VERSION 5.7 ;
BUSBITCHARS "[]" ;
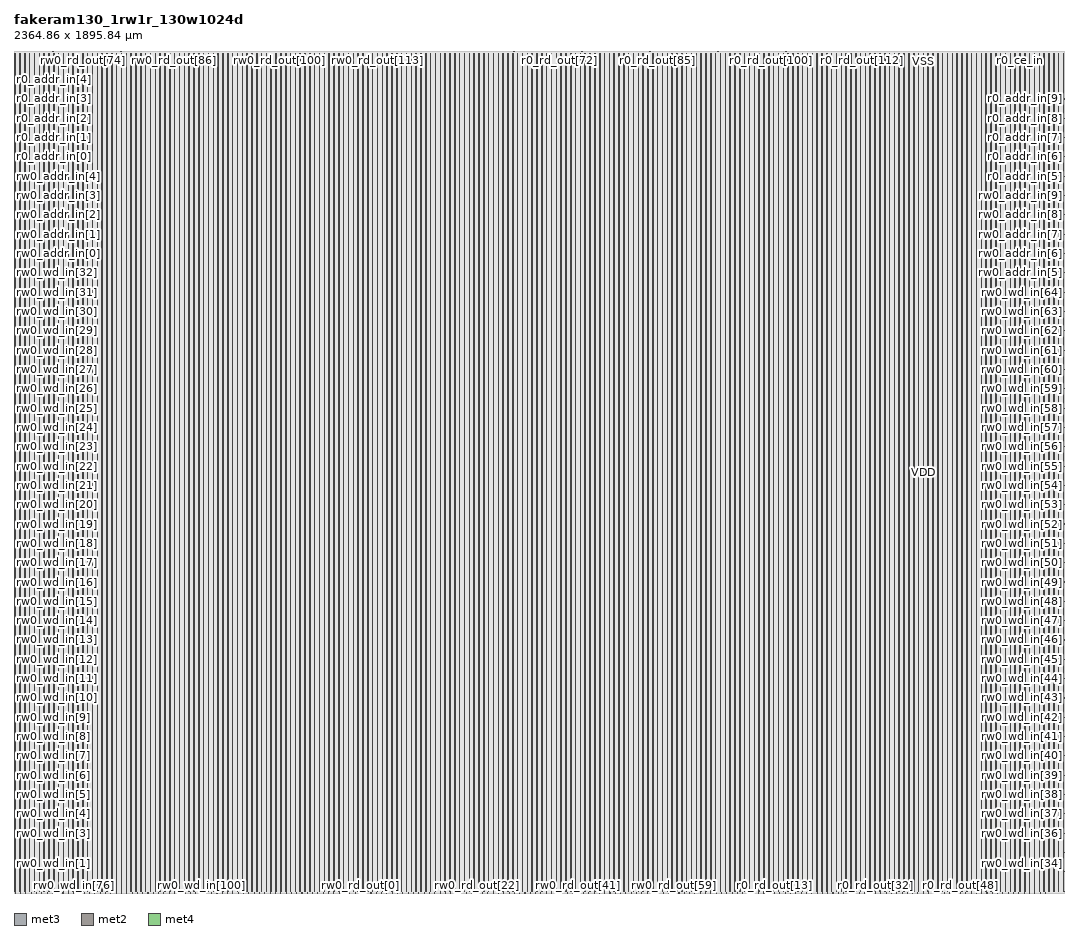
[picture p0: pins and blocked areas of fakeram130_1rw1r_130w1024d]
MACRO fakeram130_1rw1r_130w1024d
  FOREIGN fakeram130_1rw1r_130w1024d 0 0 ;
  SYMMETRY X Y R90 ;
  SIZE 2364.860 BY 1895.840 ;
  CLASS BLOCK ;
  PIN rw0_wd_in[0]
    DIRECTION INPUT ;
    USE SIGNAL ;
    SHAPE ABUTMENT ;
    PORT
      LAYER met3 ;
      RECT 0.000 3.930 0.900 4.230 ;
    END
  END rw0_wd_in[0]
  PIN rw0_wd_in[1]
    DIRECTION INPUT ;
    USE SIGNAL ;
    SHAPE ABUTMENT ;
    PORT
      LAYER met3 ;
      RECT 0.000 47.450 0.900 47.750 ;
    END
  END rw0_wd_in[1]
  PIN rw0_wd_in[2]
    DIRECTION INPUT ;
    USE SIGNAL ;
    SHAPE ABUTMENT ;
    PORT
      LAYER met3 ;
      RECT 0.000 90.970 0.900 91.270 ;
    END
  END rw0_wd_in[2]
  PIN rw0_wd_in[3]
    DIRECTION INPUT ;
    USE SIGNAL ;
    SHAPE ABUTMENT ;
    PORT
      LAYER met3 ;
      RECT 0.000 134.490 0.900 134.790 ;
    END
  END rw0_wd_in[3]
  PIN rw0_wd_in[4]
    DIRECTION INPUT ;
    USE SIGNAL ;
    SHAPE ABUTMENT ;
    PORT
      LAYER met3 ;
      RECT 0.000 178.010 0.900 178.310 ;
    END
  END rw0_wd_in[4]
  PIN rw0_wd_in[5]
    DIRECTION INPUT ;
    USE SIGNAL ;
    SHAPE ABUTMENT ;
    PORT
      LAYER met3 ;
      RECT 0.000 221.530 0.900 221.830 ;
    END
  END rw0_wd_in[5]
  PIN rw0_wd_in[6]
    DIRECTION INPUT ;
    USE SIGNAL ;
    SHAPE ABUTMENT ;
    PORT
      LAYER met3 ;
      RECT 0.000 265.050 0.900 265.350 ;
    END
  END rw0_wd_in[6]
  PIN rw0_wd_in[7]
    DIRECTION INPUT ;
    USE SIGNAL ;
    SHAPE ABUTMENT ;
    PORT
      LAYER met3 ;
      RECT 0.000 308.570 0.900 308.870 ;
    END
  END rw0_wd_in[7]
  PIN rw0_wd_in[8]
    DIRECTION INPUT ;
    USE SIGNAL ;
    SHAPE ABUTMENT ;
    PORT
      LAYER met3 ;
      RECT 0.000 352.090 0.900 352.390 ;
    END
  END rw0_wd_in[8]
  PIN rw0_wd_in[9]
    DIRECTION INPUT ;
    USE SIGNAL ;
    SHAPE ABUTMENT ;
    PORT
      LAYER met3 ;
      RECT 0.000 395.610 0.900 395.910 ;
    END
  END rw0_wd_in[9]
  PIN rw0_wd_in[10]
    DIRECTION INPUT ;
    USE SIGNAL ;
    SHAPE ABUTMENT ;
    PORT
      LAYER met3 ;
      RECT 0.000 439.130 0.900 439.430 ;
    END
  END rw0_wd_in[10]
  PIN rw0_wd_in[11]
    DIRECTION INPUT ;
    USE SIGNAL ;
    SHAPE ABUTMENT ;
    PORT
      LAYER met3 ;
      RECT 0.000 482.650 0.900 482.950 ;
    END
  END rw0_wd_in[11]
  PIN rw0_wd_in[12]
    DIRECTION INPUT ;
    USE SIGNAL ;
    SHAPE ABUTMENT ;
    PORT
      LAYER met3 ;
      RECT 0.000 526.170 0.900 526.470 ;
    END
  END rw0_wd_in[12]
  PIN rw0_wd_in[13]
    DIRECTION INPUT ;
    USE SIGNAL ;
    SHAPE ABUTMENT ;
    PORT
      LAYER met3 ;
      RECT 0.000 569.690 0.900 569.990 ;
    END
  END rw0_wd_in[13]
  PIN rw0_wd_in[14]
    DIRECTION INPUT ;
    USE SIGNAL ;
    SHAPE ABUTMENT ;
    PORT
      LAYER met3 ;
      RECT 0.000 613.210 0.900 613.510 ;
    END
  END rw0_wd_in[14]
  PIN rw0_wd_in[15]
    DIRECTION INPUT ;
    USE SIGNAL ;
    SHAPE ABUTMENT ;
    PORT
      LAYER met3 ;
      RECT 0.000 656.730 0.900 657.030 ;
    END
  END rw0_wd_in[15]
  PIN rw0_wd_in[16]
    DIRECTION INPUT ;
    USE SIGNAL ;
    SHAPE ABUTMENT ;
    PORT
      LAYER met3 ;
      RECT 0.000 700.250 0.900 700.550 ;
    END
  END rw0_wd_in[16]
  PIN rw0_wd_in[17]
    DIRECTION INPUT ;
    USE SIGNAL ;
    SHAPE ABUTMENT ;
    PORT
      LAYER met3 ;
      RECT 0.000 743.770 0.900 744.070 ;
    END
  END rw0_wd_in[17]
  PIN rw0_wd_in[18]
    DIRECTION INPUT ;
    USE SIGNAL ;
    SHAPE ABUTMENT ;
    PORT
      LAYER met3 ;
      RECT 0.000 787.290 0.900 787.590 ;
    END
  END rw0_wd_in[18]
  PIN rw0_wd_in[19]
    DIRECTION INPUT ;
    USE SIGNAL ;
    SHAPE ABUTMENT ;
    PORT
      LAYER met3 ;
      RECT 0.000 830.810 0.900 831.110 ;
    END
  END rw0_wd_in[19]
  PIN rw0_wd_in[20]
    DIRECTION INPUT ;
    USE SIGNAL ;
    SHAPE ABUTMENT ;
    PORT
      LAYER met3 ;
      RECT 0.000 874.330 0.900 874.630 ;
    END
  END rw0_wd_in[20]
  PIN rw0_wd_in[21]
    DIRECTION INPUT ;
    USE SIGNAL ;
    SHAPE ABUTMENT ;
    PORT
      LAYER met3 ;
      RECT 0.000 917.850 0.900 918.150 ;
    END
  END rw0_wd_in[21]
  PIN rw0_wd_in[22]
    DIRECTION INPUT ;
    USE SIGNAL ;
    SHAPE ABUTMENT ;
    PORT
      LAYER met3 ;
      RECT 0.000 961.370 0.900 961.670 ;
    END
  END rw0_wd_in[22]
  PIN rw0_wd_in[23]
    DIRECTION INPUT ;
    USE SIGNAL ;
    SHAPE ABUTMENT ;
    PORT
      LAYER met3 ;
      RECT 0.000 1004.890 0.900 1005.190 ;
    END
  END rw0_wd_in[23]
  PIN rw0_wd_in[24]
    DIRECTION INPUT ;
    USE SIGNAL ;
    SHAPE ABUTMENT ;
    PORT
      LAYER met3 ;
      RECT 0.000 1048.410 0.900 1048.710 ;
    END
  END rw0_wd_in[24]
  PIN rw0_wd_in[25]
    DIRECTION INPUT ;
    USE SIGNAL ;
    SHAPE ABUTMENT ;
    PORT
      LAYER met3 ;
      RECT 0.000 1091.930 0.900 1092.230 ;
    END
  END rw0_wd_in[25]
  PIN rw0_wd_in[26]
    DIRECTION INPUT ;
    USE SIGNAL ;
    SHAPE ABUTMENT ;
    PORT
      LAYER met3 ;
      RECT 0.000 1135.450 0.900 1135.750 ;
    END
  END rw0_wd_in[26]
  PIN rw0_wd_in[27]
    DIRECTION INPUT ;
    USE SIGNAL ;
    SHAPE ABUTMENT ;
    PORT
      LAYER met3 ;
      RECT 0.000 1178.970 0.900 1179.270 ;
    END
  END rw0_wd_in[27]
  PIN rw0_wd_in[28]
    DIRECTION INPUT ;
    USE SIGNAL ;
    SHAPE ABUTMENT ;
    PORT
      LAYER met3 ;
      RECT 0.000 1222.490 0.900 1222.790 ;
    END
  END rw0_wd_in[28]
  PIN rw0_wd_in[29]
    DIRECTION INPUT ;
    USE SIGNAL ;
    SHAPE ABUTMENT ;
    PORT
      LAYER met3 ;
      RECT 0.000 1266.010 0.900 1266.310 ;
    END
  END rw0_wd_in[29]
  PIN rw0_wd_in[30]
    DIRECTION INPUT ;
    USE SIGNAL ;
    SHAPE ABUTMENT ;
    PORT
      LAYER met3 ;
      RECT 0.000 1309.530 0.900 1309.830 ;
    END
  END rw0_wd_in[30]
  PIN rw0_wd_in[31]
    DIRECTION INPUT ;
    USE SIGNAL ;
    SHAPE ABUTMENT ;
    PORT
      LAYER met3 ;
      RECT 0.000 1353.050 0.900 1353.350 ;
    END
  END rw0_wd_in[31]
  PIN rw0_wd_in[32]
    DIRECTION INPUT ;
    USE SIGNAL ;
    SHAPE ABUTMENT ;
    PORT
      LAYER met3 ;
      RECT 0.000 1396.570 0.900 1396.870 ;
    END
  END rw0_wd_in[32]
  PIN rw0_wd_in[33]
    DIRECTION INPUT ;
    USE SIGNAL ;
    SHAPE ABUTMENT ;
    PORT
      LAYER met3 ;
      RECT 2363.960 3.930 2364.860 4.230 ;
    END
  END rw0_wd_in[33]
  PIN rw0_wd_in[34]
    DIRECTION INPUT ;
    USE SIGNAL ;
    SHAPE ABUTMENT ;
    PORT
      LAYER met3 ;
      RECT 2363.960 47.450 2364.860 47.750 ;
    END
  END rw0_wd_in[34]
  PIN rw0_wd_in[35]
    DIRECTION INPUT ;
    USE SIGNAL ;
    SHAPE ABUTMENT ;
    PORT
      LAYER met3 ;
      RECT 2363.960 90.970 2364.860 91.270 ;
    END
  END rw0_wd_in[35]
  PIN rw0_wd_in[36]
    DIRECTION INPUT ;
    USE SIGNAL ;
    SHAPE ABUTMENT ;
    PORT
      LAYER met3 ;
      RECT 2363.960 134.490 2364.860 134.790 ;
    END
  END rw0_wd_in[36]
  PIN rw0_wd_in[37]
    DIRECTION INPUT ;
    USE SIGNAL ;
    SHAPE ABUTMENT ;
    PORT
      LAYER met3 ;
      RECT 2363.960 178.010 2364.860 178.310 ;
    END
  END rw0_wd_in[37]
  PIN rw0_wd_in[38]
    DIRECTION INPUT ;
    USE SIGNAL ;
    SHAPE ABUTMENT ;
    PORT
      LAYER met3 ;
      RECT 2363.960 221.530 2364.860 221.830 ;
    END
  END rw0_wd_in[38]
  PIN rw0_wd_in[39]
    DIRECTION INPUT ;
    USE SIGNAL ;
    SHAPE ABUTMENT ;
    PORT
      LAYER met3 ;
      RECT 2363.960 265.050 2364.860 265.350 ;
    END
  END rw0_wd_in[39]
  PIN rw0_wd_in[40]
    DIRECTION INPUT ;
    USE SIGNAL ;
    SHAPE ABUTMENT ;
    PORT
      LAYER met3 ;
      RECT 2363.960 308.570 2364.860 308.870 ;
    END
  END rw0_wd_in[40]
  PIN rw0_wd_in[41]
    DIRECTION INPUT ;
    USE SIGNAL ;
    SHAPE ABUTMENT ;
    PORT
      LAYER met3 ;
      RECT 2363.960 352.090 2364.860 352.390 ;
    END
  END rw0_wd_in[41]
  PIN rw0_wd_in[42]
    DIRECTION INPUT ;
    USE SIGNAL ;
    SHAPE ABUTMENT ;
    PORT
      LAYER met3 ;
      RECT 2363.960 395.610 2364.860 395.910 ;
    END
  END rw0_wd_in[42]
  PIN rw0_wd_in[43]
    DIRECTION INPUT ;
    USE SIGNAL ;
    SHAPE ABUTMENT ;
    PORT
      LAYER met3 ;
      RECT 2363.960 439.130 2364.860 439.430 ;
    END
  END rw0_wd_in[43]
  PIN rw0_wd_in[44]
    DIRECTION INPUT ;
    USE SIGNAL ;
    SHAPE ABUTMENT ;
    PORT
      LAYER met3 ;
      RECT 2363.960 482.650 2364.860 482.950 ;
    END
  END rw0_wd_in[44]
  PIN rw0_wd_in[45]
    DIRECTION INPUT ;
    USE SIGNAL ;
    SHAPE ABUTMENT ;
    PORT
      LAYER met3 ;
      RECT 2363.960 526.170 2364.860 526.470 ;
    END
  END rw0_wd_in[45]
  PIN rw0_wd_in[46]
    DIRECTION INPUT ;
    USE SIGNAL ;
    SHAPE ABUTMENT ;
    PORT
      LAYER met3 ;
      RECT 2363.960 569.690 2364.860 569.990 ;
    END
  END rw0_wd_in[46]
  PIN rw0_wd_in[47]
    DIRECTION INPUT ;
    USE SIGNAL ;
    SHAPE ABUTMENT ;
    PORT
      LAYER met3 ;
      RECT 2363.960 613.210 2364.860 613.510 ;
    END
  END rw0_wd_in[47]
  PIN rw0_wd_in[48]
    DIRECTION INPUT ;
    USE SIGNAL ;
    SHAPE ABUTMENT ;
    PORT
      LAYER met3 ;
      RECT 2363.960 656.730 2364.860 657.030 ;
    END
  END rw0_wd_in[48]
  PIN rw0_wd_in[49]
    DIRECTION INPUT ;
    USE SIGNAL ;
    SHAPE ABUTMENT ;
    PORT
      LAYER met3 ;
      RECT 2363.960 700.250 2364.860 700.550 ;
    END
  END rw0_wd_in[49]
  PIN rw0_wd_in[50]
    DIRECTION INPUT ;
    USE SIGNAL ;
    SHAPE ABUTMENT ;
    PORT
      LAYER met3 ;
      RECT 2363.960 743.770 2364.860 744.070 ;
    END
  END rw0_wd_in[50]
  PIN rw0_wd_in[51]
    DIRECTION INPUT ;
    USE SIGNAL ;
    SHAPE ABUTMENT ;
    PORT
      LAYER met3 ;
      RECT 2363.960 787.290 2364.860 787.590 ;
    END
  END rw0_wd_in[51]
  PIN rw0_wd_in[52]
    DIRECTION INPUT ;
    USE SIGNAL ;
    SHAPE ABUTMENT ;
    PORT
      LAYER met3 ;
      RECT 2363.960 830.810 2364.860 831.110 ;
    END
  END rw0_wd_in[52]
  PIN rw0_wd_in[53]
    DIRECTION INPUT ;
    USE SIGNAL ;
    SHAPE ABUTMENT ;
    PORT
      LAYER met3 ;
      RECT 2363.960 874.330 2364.860 874.630 ;
    END
  END rw0_wd_in[53]
  PIN rw0_wd_in[54]
    DIRECTION INPUT ;
    USE SIGNAL ;
    SHAPE ABUTMENT ;
    PORT
      LAYER met3 ;
      RECT 2363.960 917.850 2364.860 918.150 ;
    END
  END rw0_wd_in[54]
  PIN rw0_wd_in[55]
    DIRECTION INPUT ;
    USE SIGNAL ;
    SHAPE ABUTMENT ;
    PORT
      LAYER met3 ;
      RECT 2363.960 961.370 2364.860 961.670 ;
    END
  END rw0_wd_in[55]
  PIN rw0_wd_in[56]
    DIRECTION INPUT ;
    USE SIGNAL ;
    SHAPE ABUTMENT ;
    PORT
      LAYER met3 ;
      RECT 2363.960 1004.890 2364.860 1005.190 ;
    END
  END rw0_wd_in[56]
  PIN rw0_wd_in[57]
    DIRECTION INPUT ;
    USE SIGNAL ;
    SHAPE ABUTMENT ;
    PORT
      LAYER met3 ;
      RECT 2363.960 1048.410 2364.860 1048.710 ;
    END
  END rw0_wd_in[57]
  PIN rw0_wd_in[58]
    DIRECTION INPUT ;
    USE SIGNAL ;
    SHAPE ABUTMENT ;
    PORT
      LAYER met3 ;
      RECT 2363.960 1091.930 2364.860 1092.230 ;
    END
  END rw0_wd_in[58]
  PIN rw0_wd_in[59]
    DIRECTION INPUT ;
    USE SIGNAL ;
    SHAPE ABUTMENT ;
    PORT
      LAYER met3 ;
      RECT 2363.960 1135.450 2364.860 1135.750 ;
    END
  END rw0_wd_in[59]
  PIN rw0_wd_in[60]
    DIRECTION INPUT ;
    USE SIGNAL ;
    SHAPE ABUTMENT ;
    PORT
      LAYER met3 ;
      RECT 2363.960 1178.970 2364.860 1179.270 ;
    END
  END rw0_wd_in[60]
  PIN rw0_wd_in[61]
    DIRECTION INPUT ;
    USE SIGNAL ;
    SHAPE ABUTMENT ;
    PORT
      LAYER met3 ;
      RECT 2363.960 1222.490 2364.860 1222.790 ;
    END
  END rw0_wd_in[61]
  PIN rw0_wd_in[62]
    DIRECTION INPUT ;
    USE SIGNAL ;
    SHAPE ABUTMENT ;
    PORT
      LAYER met3 ;
      RECT 2363.960 1266.010 2364.860 1266.310 ;
    END
  END rw0_wd_in[62]
  PIN rw0_wd_in[63]
    DIRECTION INPUT ;
    USE SIGNAL ;
    SHAPE ABUTMENT ;
    PORT
      LAYER met3 ;
      RECT 2363.960 1309.530 2364.860 1309.830 ;
    END
  END rw0_wd_in[63]
  PIN rw0_wd_in[64]
    DIRECTION INPUT ;
    USE SIGNAL ;
    SHAPE ABUTMENT ;
    PORT
      LAYER met3 ;
      RECT 2363.960 1353.050 2364.860 1353.350 ;
    END
  END rw0_wd_in[64]
  PIN rw0_wd_in[65]
    DIRECTION INPUT ;
    USE SIGNAL ;
    SHAPE ABUTMENT ;
    PORT
      LAYER met2 ;
      RECT 2.690 0.000 2.830 0.420 ;
    END
  END rw0_wd_in[65]
  PIN rw0_wd_in[66]
    DIRECTION INPUT ;
    USE SIGNAL ;
    SHAPE ABUTMENT ;
    PORT
      LAYER met2 ;
      RECT 14.650 0.000 14.790 0.420 ;
    END
  END rw0_wd_in[66]
  PIN rw0_wd_in[67]
    DIRECTION INPUT ;
    USE SIGNAL ;
    SHAPE ABUTMENT ;
    PORT
      LAYER met2 ;
      RECT 26.610 0.000 26.750 0.420 ;
    END
  END rw0_wd_in[67]
  PIN rw0_wd_in[68]
    DIRECTION INPUT ;
    USE SIGNAL ;
    SHAPE ABUTMENT ;
    PORT
      LAYER met2 ;
      RECT 38.570 0.000 38.710 0.420 ;
    END
  END rw0_wd_in[68]
  PIN rw0_wd_in[69]
    DIRECTION INPUT ;
    USE SIGNAL ;
    SHAPE ABUTMENT ;
    PORT
      LAYER met2 ;
      RECT 50.530 0.000 50.670 0.420 ;
    END
  END rw0_wd_in[69]
  PIN rw0_wd_in[70]
    DIRECTION INPUT ;
    USE SIGNAL ;
    SHAPE ABUTMENT ;
    PORT
      LAYER met2 ;
      RECT 62.490 0.000 62.630 0.420 ;
    END
  END rw0_wd_in[70]
  PIN rw0_wd_in[71]
    DIRECTION INPUT ;
    USE SIGNAL ;
    SHAPE ABUTMENT ;
    PORT
      LAYER met2 ;
      RECT 74.450 0.000 74.590 0.420 ;
    END
  END rw0_wd_in[71]
  PIN rw0_wd_in[72]
    DIRECTION INPUT ;
    USE SIGNAL ;
    SHAPE ABUTMENT ;
    PORT
      LAYER met2 ;
      RECT 86.410 0.000 86.550 0.420 ;
    END
  END rw0_wd_in[72]
  PIN rw0_wd_in[73]
    DIRECTION INPUT ;
    USE SIGNAL ;
    SHAPE ABUTMENT ;
    PORT
      LAYER met2 ;
      RECT 98.370 0.000 98.510 0.420 ;
    END
  END rw0_wd_in[73]
  PIN rw0_wd_in[74]
    DIRECTION INPUT ;
    USE SIGNAL ;
    SHAPE ABUTMENT ;
    PORT
      LAYER met2 ;
      RECT 110.330 0.000 110.470 0.420 ;
    END
  END rw0_wd_in[74]
  PIN rw0_wd_in[75]
    DIRECTION INPUT ;
    USE SIGNAL ;
    SHAPE ABUTMENT ;
    PORT
      LAYER met2 ;
      RECT 122.290 0.000 122.430 0.420 ;
    END
  END rw0_wd_in[75]
  PIN rw0_wd_in[76]
    DIRECTION INPUT ;
    USE SIGNAL ;
    SHAPE ABUTMENT ;
    PORT
      LAYER met2 ;
      RECT 134.250 0.000 134.390 0.420 ;
    END
  END rw0_wd_in[76]
  PIN rw0_wd_in[77]
    DIRECTION INPUT ;
    USE SIGNAL ;
    SHAPE ABUTMENT ;
    PORT
      LAYER met2 ;
      RECT 146.210 0.000 146.350 0.420 ;
    END
  END rw0_wd_in[77]
  PIN rw0_wd_in[78]
    DIRECTION INPUT ;
    USE SIGNAL ;
    SHAPE ABUTMENT ;
    PORT
      LAYER met2 ;
      RECT 158.170 0.000 158.310 0.420 ;
    END
  END rw0_wd_in[78]
  PIN rw0_wd_in[79]
    DIRECTION INPUT ;
    USE SIGNAL ;
    SHAPE ABUTMENT ;
    PORT
      LAYER met2 ;
      RECT 170.130 0.000 170.270 0.420 ;
    END
  END rw0_wd_in[79]
  PIN rw0_wd_in[80]
    DIRECTION INPUT ;
    USE SIGNAL ;
    SHAPE ABUTMENT ;
    PORT
      LAYER met2 ;
      RECT 182.090 0.000 182.230 0.420 ;
    END
  END rw0_wd_in[80]
  PIN rw0_wd_in[81]
    DIRECTION INPUT ;
    USE SIGNAL ;
    SHAPE ABUTMENT ;
    PORT
      LAYER met2 ;
      RECT 194.050 0.000 194.190 0.420 ;
    END
  END rw0_wd_in[81]
  PIN rw0_wd_in[82]
    DIRECTION INPUT ;
    USE SIGNAL ;
    SHAPE ABUTMENT ;
    PORT
      LAYER met2 ;
      RECT 206.010 0.000 206.150 0.420 ;
    END
  END rw0_wd_in[82]
  PIN rw0_wd_in[83]
    DIRECTION INPUT ;
    USE SIGNAL ;
    SHAPE ABUTMENT ;
    PORT
      LAYER met2 ;
      RECT 217.970 0.000 218.110 0.420 ;
    END
  END rw0_wd_in[83]
  PIN rw0_wd_in[84]
    DIRECTION INPUT ;
    USE SIGNAL ;
    SHAPE ABUTMENT ;
    PORT
      LAYER met2 ;
      RECT 229.930 0.000 230.070 0.420 ;
    END
  END rw0_wd_in[84]
  PIN rw0_wd_in[85]
    DIRECTION INPUT ;
    USE SIGNAL ;
    SHAPE ABUTMENT ;
    PORT
      LAYER met2 ;
      RECT 241.890 0.000 242.030 0.420 ;
    END
  END rw0_wd_in[85]
  PIN rw0_wd_in[86]
    DIRECTION INPUT ;
    USE SIGNAL ;
    SHAPE ABUTMENT ;
    PORT
      LAYER met2 ;
      RECT 253.850 0.000 253.990 0.420 ;
    END
  END rw0_wd_in[86]
  PIN rw0_wd_in[87]
    DIRECTION INPUT ;
    USE SIGNAL ;
    SHAPE ABUTMENT ;
    PORT
      LAYER met2 ;
      RECT 265.810 0.000 265.950 0.420 ;
    END
  END rw0_wd_in[87]
  PIN rw0_wd_in[88]
    DIRECTION INPUT ;
    USE SIGNAL ;
    SHAPE ABUTMENT ;
    PORT
      LAYER met2 ;
      RECT 277.770 0.000 277.910 0.420 ;
    END
  END rw0_wd_in[88]
  PIN rw0_wd_in[89]
    DIRECTION INPUT ;
    USE SIGNAL ;
    SHAPE ABUTMENT ;
    PORT
      LAYER met2 ;
      RECT 289.730 0.000 289.870 0.420 ;
    END
  END rw0_wd_in[89]
  PIN rw0_wd_in[90]
    DIRECTION INPUT ;
    USE SIGNAL ;
    SHAPE ABUTMENT ;
    PORT
      LAYER met2 ;
      RECT 301.690 0.000 301.830 0.420 ;
    END
  END rw0_wd_in[90]
  PIN rw0_wd_in[91]
    DIRECTION INPUT ;
    USE SIGNAL ;
    SHAPE ABUTMENT ;
    PORT
      LAYER met2 ;
      RECT 313.650 0.000 313.790 0.420 ;
    END
  END rw0_wd_in[91]
  PIN rw0_wd_in[92]
    DIRECTION INPUT ;
    USE SIGNAL ;
    SHAPE ABUTMENT ;
    PORT
      LAYER met2 ;
      RECT 325.610 0.000 325.750 0.420 ;
    END
  END rw0_wd_in[92]
  PIN rw0_wd_in[93]
    DIRECTION INPUT ;
    USE SIGNAL ;
    SHAPE ABUTMENT ;
    PORT
      LAYER met2 ;
      RECT 337.570 0.000 337.710 0.420 ;
    END
  END rw0_wd_in[93]
  PIN rw0_wd_in[94]
    DIRECTION INPUT ;
    USE SIGNAL ;
    SHAPE ABUTMENT ;
    PORT
      LAYER met2 ;
      RECT 349.530 0.000 349.670 0.420 ;
    END
  END rw0_wd_in[94]
  PIN rw0_wd_in[95]
    DIRECTION INPUT ;
    USE SIGNAL ;
    SHAPE ABUTMENT ;
    PORT
      LAYER met2 ;
      RECT 361.490 0.000 361.630 0.420 ;
    END
  END rw0_wd_in[95]
  PIN rw0_wd_in[96]
    DIRECTION INPUT ;
    USE SIGNAL ;
    SHAPE ABUTMENT ;
    PORT
      LAYER met2 ;
      RECT 373.450 0.000 373.590 0.420 ;
    END
  END rw0_wd_in[96]
  PIN rw0_wd_in[97]
    DIRECTION INPUT ;
    USE SIGNAL ;
    SHAPE ABUTMENT ;
    PORT
      LAYER met2 ;
      RECT 385.410 0.000 385.550 0.420 ;
    END
  END rw0_wd_in[97]
  PIN rw0_wd_in[98]
    DIRECTION INPUT ;
    USE SIGNAL ;
    SHAPE ABUTMENT ;
    PORT
      LAYER met2 ;
      RECT 397.370 0.000 397.510 0.420 ;
    END
  END rw0_wd_in[98]
  PIN rw0_wd_in[99]
    DIRECTION INPUT ;
    USE SIGNAL ;
    SHAPE ABUTMENT ;
    PORT
      LAYER met2 ;
      RECT 409.330 0.000 409.470 0.420 ;
    END
  END rw0_wd_in[99]
  PIN rw0_wd_in[100]
    DIRECTION INPUT ;
    USE SIGNAL ;
    SHAPE ABUTMENT ;
    PORT
      LAYER met2 ;
      RECT 421.290 0.000 421.430 0.420 ;
    END
  END rw0_wd_in[100]
  PIN rw0_wd_in[101]
    DIRECTION INPUT ;
    USE SIGNAL ;
    SHAPE ABUTMENT ;
    PORT
      LAYER met2 ;
      RECT 433.250 0.000 433.390 0.420 ;
    END
  END rw0_wd_in[101]
  PIN rw0_wd_in[102]
    DIRECTION INPUT ;
    USE SIGNAL ;
    SHAPE ABUTMENT ;
    PORT
      LAYER met2 ;
      RECT 445.210 0.000 445.350 0.420 ;
    END
  END rw0_wd_in[102]
  PIN rw0_wd_in[103]
    DIRECTION INPUT ;
    USE SIGNAL ;
    SHAPE ABUTMENT ;
    PORT
      LAYER met2 ;
      RECT 457.170 0.000 457.310 0.420 ;
    END
  END rw0_wd_in[103]
  PIN rw0_wd_in[104]
    DIRECTION INPUT ;
    USE SIGNAL ;
    SHAPE ABUTMENT ;
    PORT
      LAYER met2 ;
      RECT 469.130 0.000 469.270 0.420 ;
    END
  END rw0_wd_in[104]
  PIN rw0_wd_in[105]
    DIRECTION INPUT ;
    USE SIGNAL ;
    SHAPE ABUTMENT ;
    PORT
      LAYER met2 ;
      RECT 481.090 0.000 481.230 0.420 ;
    END
  END rw0_wd_in[105]
  PIN rw0_wd_in[106]
    DIRECTION INPUT ;
    USE SIGNAL ;
    SHAPE ABUTMENT ;
    PORT
      LAYER met2 ;
      RECT 493.050 0.000 493.190 0.420 ;
    END
  END rw0_wd_in[106]
  PIN rw0_wd_in[107]
    DIRECTION INPUT ;
    USE SIGNAL ;
    SHAPE ABUTMENT ;
    PORT
      LAYER met2 ;
      RECT 505.010 0.000 505.150 0.420 ;
    END
  END rw0_wd_in[107]
  PIN rw0_wd_in[108]
    DIRECTION INPUT ;
    USE SIGNAL ;
    SHAPE ABUTMENT ;
    PORT
      LAYER met2 ;
      RECT 516.970 0.000 517.110 0.420 ;
    END
  END rw0_wd_in[108]
  PIN rw0_wd_in[109]
    DIRECTION INPUT ;
    USE SIGNAL ;
    SHAPE ABUTMENT ;
    PORT
      LAYER met2 ;
      RECT 528.930 0.000 529.070 0.420 ;
    END
  END rw0_wd_in[109]
  PIN rw0_wd_in[110]
    DIRECTION INPUT ;
    USE SIGNAL ;
    SHAPE ABUTMENT ;
    PORT
      LAYER met2 ;
      RECT 540.890 0.000 541.030 0.420 ;
    END
  END rw0_wd_in[110]
  PIN rw0_wd_in[111]
    DIRECTION INPUT ;
    USE SIGNAL ;
    SHAPE ABUTMENT ;
    PORT
      LAYER met2 ;
      RECT 552.850 0.000 552.990 0.420 ;
    END
  END rw0_wd_in[111]
  PIN rw0_wd_in[112]
    DIRECTION INPUT ;
    USE SIGNAL ;
    SHAPE ABUTMENT ;
    PORT
      LAYER met2 ;
      RECT 564.810 0.000 564.950 0.420 ;
    END
  END rw0_wd_in[112]
  PIN rw0_wd_in[113]
    DIRECTION INPUT ;
    USE SIGNAL ;
    SHAPE ABUTMENT ;
    PORT
      LAYER met2 ;
      RECT 576.770 0.000 576.910 0.420 ;
    END
  END rw0_wd_in[113]
  PIN rw0_wd_in[114]
    DIRECTION INPUT ;
    USE SIGNAL ;
    SHAPE ABUTMENT ;
    PORT
      LAYER met2 ;
      RECT 588.730 0.000 588.870 0.420 ;
    END
  END rw0_wd_in[114]
  PIN rw0_wd_in[115]
    DIRECTION INPUT ;
    USE SIGNAL ;
    SHAPE ABUTMENT ;
    PORT
      LAYER met2 ;
      RECT 600.690 0.000 600.830 0.420 ;
    END
  END rw0_wd_in[115]
  PIN rw0_wd_in[116]
    DIRECTION INPUT ;
    USE SIGNAL ;
    SHAPE ABUTMENT ;
    PORT
      LAYER met2 ;
      RECT 612.650 0.000 612.790 0.420 ;
    END
  END rw0_wd_in[116]
  PIN rw0_wd_in[117]
    DIRECTION INPUT ;
    USE SIGNAL ;
    SHAPE ABUTMENT ;
    PORT
      LAYER met2 ;
      RECT 624.610 0.000 624.750 0.420 ;
    END
  END rw0_wd_in[117]
  PIN rw0_wd_in[118]
    DIRECTION INPUT ;
    USE SIGNAL ;
    SHAPE ABUTMENT ;
    PORT
      LAYER met2 ;
      RECT 636.570 0.000 636.710 0.420 ;
    END
  END rw0_wd_in[118]
  PIN rw0_wd_in[119]
    DIRECTION INPUT ;
    USE SIGNAL ;
    SHAPE ABUTMENT ;
    PORT
      LAYER met2 ;
      RECT 648.530 0.000 648.670 0.420 ;
    END
  END rw0_wd_in[119]
  PIN rw0_wd_in[120]
    DIRECTION INPUT ;
    USE SIGNAL ;
    SHAPE ABUTMENT ;
    PORT
      LAYER met2 ;
      RECT 660.490 0.000 660.630 0.420 ;
    END
  END rw0_wd_in[120]
  PIN rw0_wd_in[121]
    DIRECTION INPUT ;
    USE SIGNAL ;
    SHAPE ABUTMENT ;
    PORT
      LAYER met2 ;
      RECT 672.450 0.000 672.590 0.420 ;
    END
  END rw0_wd_in[121]
  PIN rw0_wd_in[122]
    DIRECTION INPUT ;
    USE SIGNAL ;
    SHAPE ABUTMENT ;
    PORT
      LAYER met2 ;
      RECT 684.410 0.000 684.550 0.420 ;
    END
  END rw0_wd_in[122]
  PIN rw0_wd_in[123]
    DIRECTION INPUT ;
    USE SIGNAL ;
    SHAPE ABUTMENT ;
    PORT
      LAYER met2 ;
      RECT 696.370 0.000 696.510 0.420 ;
    END
  END rw0_wd_in[123]
  PIN rw0_wd_in[124]
    DIRECTION INPUT ;
    USE SIGNAL ;
    SHAPE ABUTMENT ;
    PORT
      LAYER met2 ;
      RECT 708.330 0.000 708.470 0.420 ;
    END
  END rw0_wd_in[124]
  PIN rw0_wd_in[125]
    DIRECTION INPUT ;
    USE SIGNAL ;
    SHAPE ABUTMENT ;
    PORT
      LAYER met2 ;
      RECT 720.290 0.000 720.430 0.420 ;
    END
  END rw0_wd_in[125]
  PIN rw0_wd_in[126]
    DIRECTION INPUT ;
    USE SIGNAL ;
    SHAPE ABUTMENT ;
    PORT
      LAYER met2 ;
      RECT 732.250 0.000 732.390 0.420 ;
    END
  END rw0_wd_in[126]
  PIN rw0_wd_in[127]
    DIRECTION INPUT ;
    USE SIGNAL ;
    SHAPE ABUTMENT ;
    PORT
      LAYER met2 ;
      RECT 744.210 0.000 744.350 0.420 ;
    END
  END rw0_wd_in[127]
  PIN rw0_wd_in[128]
    DIRECTION INPUT ;
    USE SIGNAL ;
    SHAPE ABUTMENT ;
    PORT
      LAYER met2 ;
      RECT 756.170 0.000 756.310 0.420 ;
    END
  END rw0_wd_in[128]
  PIN rw0_wd_in[129]
    DIRECTION INPUT ;
    USE SIGNAL ;
    SHAPE ABUTMENT ;
    PORT
      LAYER met2 ;
      RECT 768.130 0.000 768.270 0.420 ;
    END
  END rw0_wd_in[129]
  PIN rw0_rd_out[0]
    DIRECTION OUTPUT ;
    USE SIGNAL ;
    SHAPE ABUTMENT ;
    PORT
      LAYER met2 ;
      RECT 780.090 0.000 780.230 0.420 ;
    END
  END rw0_rd_out[0]
  PIN rw0_rd_out[1]
    DIRECTION OUTPUT ;
    USE SIGNAL ;
    SHAPE ABUTMENT ;
    PORT
      LAYER met2 ;
      RECT 792.050 0.000 792.190 0.420 ;
    END
  END rw0_rd_out[1]
  PIN rw0_rd_out[2]
    DIRECTION OUTPUT ;
    USE SIGNAL ;
    SHAPE ABUTMENT ;
    PORT
      LAYER met2 ;
      RECT 804.010 0.000 804.150 0.420 ;
    END
  END rw0_rd_out[2]
  PIN rw0_rd_out[3]
    DIRECTION OUTPUT ;
    USE SIGNAL ;
    SHAPE ABUTMENT ;
    PORT
      LAYER met2 ;
      RECT 815.970 0.000 816.110 0.420 ;
    END
  END rw0_rd_out[3]
  PIN rw0_rd_out[4]
    DIRECTION OUTPUT ;
    USE SIGNAL ;
    SHAPE ABUTMENT ;
    PORT
      LAYER met2 ;
      RECT 827.930 0.000 828.070 0.420 ;
    END
  END rw0_rd_out[4]
  PIN rw0_rd_out[5]
    DIRECTION OUTPUT ;
    USE SIGNAL ;
    SHAPE ABUTMENT ;
    PORT
      LAYER met2 ;
      RECT 839.890 0.000 840.030 0.420 ;
    END
  END rw0_rd_out[5]
  PIN rw0_rd_out[6]
    DIRECTION OUTPUT ;
    USE SIGNAL ;
    SHAPE ABUTMENT ;
    PORT
      LAYER met2 ;
      RECT 851.850 0.000 851.990 0.420 ;
    END
  END rw0_rd_out[6]
  PIN rw0_rd_out[7]
    DIRECTION OUTPUT ;
    USE SIGNAL ;
    SHAPE ABUTMENT ;
    PORT
      LAYER met2 ;
      RECT 863.810 0.000 863.950 0.420 ;
    END
  END rw0_rd_out[7]
  PIN rw0_rd_out[8]
    DIRECTION OUTPUT ;
    USE SIGNAL ;
    SHAPE ABUTMENT ;
    PORT
      LAYER met2 ;
      RECT 875.770 0.000 875.910 0.420 ;
    END
  END rw0_rd_out[8]
  PIN rw0_rd_out[9]
    DIRECTION OUTPUT ;
    USE SIGNAL ;
    SHAPE ABUTMENT ;
    PORT
      LAYER met2 ;
      RECT 887.730 0.000 887.870 0.420 ;
    END
  END rw0_rd_out[9]
  PIN rw0_rd_out[10]
    DIRECTION OUTPUT ;
    USE SIGNAL ;
    SHAPE ABUTMENT ;
    PORT
      LAYER met2 ;
      RECT 899.690 0.000 899.830 0.420 ;
    END
  END rw0_rd_out[10]
  PIN rw0_rd_out[11]
    DIRECTION OUTPUT ;
    USE SIGNAL ;
    SHAPE ABUTMENT ;
    PORT
      LAYER met2 ;
      RECT 911.650 0.000 911.790 0.420 ;
    END
  END rw0_rd_out[11]
  PIN rw0_rd_out[12]
    DIRECTION OUTPUT ;
    USE SIGNAL ;
    SHAPE ABUTMENT ;
    PORT
      LAYER met2 ;
      RECT 923.610 0.000 923.750 0.420 ;
    END
  END rw0_rd_out[12]
  PIN rw0_rd_out[13]
    DIRECTION OUTPUT ;
    USE SIGNAL ;
    SHAPE ABUTMENT ;
    PORT
      LAYER met2 ;
      RECT 935.570 0.000 935.710 0.420 ;
    END
  END rw0_rd_out[13]
  PIN rw0_rd_out[14]
    DIRECTION OUTPUT ;
    USE SIGNAL ;
    SHAPE ABUTMENT ;
    PORT
      LAYER met2 ;
      RECT 947.530 0.000 947.670 0.420 ;
    END
  END rw0_rd_out[14]
  PIN rw0_rd_out[15]
    DIRECTION OUTPUT ;
    USE SIGNAL ;
    SHAPE ABUTMENT ;
    PORT
      LAYER met2 ;
      RECT 959.490 0.000 959.630 0.420 ;
    END
  END rw0_rd_out[15]
  PIN rw0_rd_out[16]
    DIRECTION OUTPUT ;
    USE SIGNAL ;
    SHAPE ABUTMENT ;
    PORT
      LAYER met2 ;
      RECT 971.450 0.000 971.590 0.420 ;
    END
  END rw0_rd_out[16]
  PIN rw0_rd_out[17]
    DIRECTION OUTPUT ;
    USE SIGNAL ;
    SHAPE ABUTMENT ;
    PORT
      LAYER met2 ;
      RECT 983.410 0.000 983.550 0.420 ;
    END
  END rw0_rd_out[17]
  PIN rw0_rd_out[18]
    DIRECTION OUTPUT ;
    USE SIGNAL ;
    SHAPE ABUTMENT ;
    PORT
      LAYER met2 ;
      RECT 995.370 0.000 995.510 0.420 ;
    END
  END rw0_rd_out[18]
  PIN rw0_rd_out[19]
    DIRECTION OUTPUT ;
    USE SIGNAL ;
    SHAPE ABUTMENT ;
    PORT
      LAYER met2 ;
      RECT 1007.330 0.000 1007.470 0.420 ;
    END
  END rw0_rd_out[19]
  PIN rw0_rd_out[20]
    DIRECTION OUTPUT ;
    USE SIGNAL ;
    SHAPE ABUTMENT ;
    PORT
      LAYER met2 ;
      RECT 1019.290 0.000 1019.430 0.420 ;
    END
  END rw0_rd_out[20]
  PIN rw0_rd_out[21]
    DIRECTION OUTPUT ;
    USE SIGNAL ;
    SHAPE ABUTMENT ;
    PORT
      LAYER met2 ;
      RECT 1031.250 0.000 1031.390 0.420 ;
    END
  END rw0_rd_out[21]
  PIN rw0_rd_out[22]
    DIRECTION OUTPUT ;
    USE SIGNAL ;
    SHAPE ABUTMENT ;
    PORT
      LAYER met2 ;
      RECT 1043.210 0.000 1043.350 0.420 ;
    END
  END rw0_rd_out[22]
  PIN rw0_rd_out[23]
    DIRECTION OUTPUT ;
    USE SIGNAL ;
    SHAPE ABUTMENT ;
    PORT
      LAYER met2 ;
      RECT 1055.170 0.000 1055.310 0.420 ;
    END
  END rw0_rd_out[23]
  PIN rw0_rd_out[24]
    DIRECTION OUTPUT ;
    USE SIGNAL ;
    SHAPE ABUTMENT ;
    PORT
      LAYER met2 ;
      RECT 1067.130 0.000 1067.270 0.420 ;
    END
  END rw0_rd_out[24]
  PIN rw0_rd_out[25]
    DIRECTION OUTPUT ;
    USE SIGNAL ;
    SHAPE ABUTMENT ;
    PORT
      LAYER met2 ;
      RECT 1079.090 0.000 1079.230 0.420 ;
    END
  END rw0_rd_out[25]
  PIN rw0_rd_out[26]
    DIRECTION OUTPUT ;
    USE SIGNAL ;
    SHAPE ABUTMENT ;
    PORT
      LAYER met2 ;
      RECT 1091.050 0.000 1091.190 0.420 ;
    END
  END rw0_rd_out[26]
  PIN rw0_rd_out[27]
    DIRECTION OUTPUT ;
    USE SIGNAL ;
    SHAPE ABUTMENT ;
    PORT
      LAYER met2 ;
      RECT 1103.010 0.000 1103.150 0.420 ;
    END
  END rw0_rd_out[27]
  PIN rw0_rd_out[28]
    DIRECTION OUTPUT ;
    USE SIGNAL ;
    SHAPE ABUTMENT ;
    PORT
      LAYER met2 ;
      RECT 1114.970 0.000 1115.110 0.420 ;
    END
  END rw0_rd_out[28]
  PIN rw0_rd_out[29]
    DIRECTION OUTPUT ;
    USE SIGNAL ;
    SHAPE ABUTMENT ;
    PORT
      LAYER met2 ;
      RECT 1126.930 0.000 1127.070 0.420 ;
    END
  END rw0_rd_out[29]
  PIN rw0_rd_out[30]
    DIRECTION OUTPUT ;
    USE SIGNAL ;
    SHAPE ABUTMENT ;
    PORT
      LAYER met2 ;
      RECT 1138.890 0.000 1139.030 0.420 ;
    END
  END rw0_rd_out[30]
  PIN rw0_rd_out[31]
    DIRECTION OUTPUT ;
    USE SIGNAL ;
    SHAPE ABUTMENT ;
    PORT
      LAYER met2 ;
      RECT 1150.850 0.000 1150.990 0.420 ;
    END
  END rw0_rd_out[31]
  PIN rw0_rd_out[32]
    DIRECTION OUTPUT ;
    USE SIGNAL ;
    SHAPE ABUTMENT ;
    PORT
      LAYER met2 ;
      RECT 1162.810 0.000 1162.950 0.420 ;
    END
  END rw0_rd_out[32]
  PIN rw0_rd_out[33]
    DIRECTION OUTPUT ;
    USE SIGNAL ;
    SHAPE ABUTMENT ;
    PORT
      LAYER met2 ;
      RECT 1174.770 0.000 1174.910 0.420 ;
    END
  END rw0_rd_out[33]
  PIN rw0_rd_out[34]
    DIRECTION OUTPUT ;
    USE SIGNAL ;
    SHAPE ABUTMENT ;
    PORT
      LAYER met2 ;
      RECT 1186.730 0.000 1186.870 0.420 ;
    END
  END rw0_rd_out[34]
  PIN rw0_rd_out[35]
    DIRECTION OUTPUT ;
    USE SIGNAL ;
    SHAPE ABUTMENT ;
    PORT
      LAYER met2 ;
      RECT 1198.690 0.000 1198.830 0.420 ;
    END
  END rw0_rd_out[35]
  PIN rw0_rd_out[36]
    DIRECTION OUTPUT ;
    USE SIGNAL ;
    SHAPE ABUTMENT ;
    PORT
      LAYER met2 ;
      RECT 1210.650 0.000 1210.790 0.420 ;
    END
  END rw0_rd_out[36]
  PIN rw0_rd_out[37]
    DIRECTION OUTPUT ;
    USE SIGNAL ;
    SHAPE ABUTMENT ;
    PORT
      LAYER met2 ;
      RECT 1222.610 0.000 1222.750 0.420 ;
    END
  END rw0_rd_out[37]
  PIN rw0_rd_out[38]
    DIRECTION OUTPUT ;
    USE SIGNAL ;
    SHAPE ABUTMENT ;
    PORT
      LAYER met2 ;
      RECT 1234.570 0.000 1234.710 0.420 ;
    END
  END rw0_rd_out[38]
  PIN rw0_rd_out[39]
    DIRECTION OUTPUT ;
    USE SIGNAL ;
    SHAPE ABUTMENT ;
    PORT
      LAYER met2 ;
      RECT 1246.530 0.000 1246.670 0.420 ;
    END
  END rw0_rd_out[39]
  PIN rw0_rd_out[40]
    DIRECTION OUTPUT ;
    USE SIGNAL ;
    SHAPE ABUTMENT ;
    PORT
      LAYER met2 ;
      RECT 1258.490 0.000 1258.630 0.420 ;
    END
  END rw0_rd_out[40]
  PIN rw0_rd_out[41]
    DIRECTION OUTPUT ;
    USE SIGNAL ;
    SHAPE ABUTMENT ;
    PORT
      LAYER met2 ;
      RECT 1270.450 0.000 1270.590 0.420 ;
    END
  END rw0_rd_out[41]
  PIN rw0_rd_out[42]
    DIRECTION OUTPUT ;
    USE SIGNAL ;
    SHAPE ABUTMENT ;
    PORT
      LAYER met2 ;
      RECT 1282.410 0.000 1282.550 0.420 ;
    END
  END rw0_rd_out[42]
  PIN rw0_rd_out[43]
    DIRECTION OUTPUT ;
    USE SIGNAL ;
    SHAPE ABUTMENT ;
    PORT
      LAYER met2 ;
      RECT 1294.370 0.000 1294.510 0.420 ;
    END
  END rw0_rd_out[43]
  PIN rw0_rd_out[44]
    DIRECTION OUTPUT ;
    USE SIGNAL ;
    SHAPE ABUTMENT ;
    PORT
      LAYER met2 ;
      RECT 1306.330 0.000 1306.470 0.420 ;
    END
  END rw0_rd_out[44]
  PIN rw0_rd_out[45]
    DIRECTION OUTPUT ;
    USE SIGNAL ;
    SHAPE ABUTMENT ;
    PORT
      LAYER met2 ;
      RECT 1318.290 0.000 1318.430 0.420 ;
    END
  END rw0_rd_out[45]
  PIN rw0_rd_out[46]
    DIRECTION OUTPUT ;
    USE SIGNAL ;
    SHAPE ABUTMENT ;
    PORT
      LAYER met2 ;
      RECT 1330.250 0.000 1330.390 0.420 ;
    END
  END rw0_rd_out[46]
  PIN rw0_rd_out[47]
    DIRECTION OUTPUT ;
    USE SIGNAL ;
    SHAPE ABUTMENT ;
    PORT
      LAYER met2 ;
      RECT 1342.210 0.000 1342.350 0.420 ;
    END
  END rw0_rd_out[47]
  PIN rw0_rd_out[48]
    DIRECTION OUTPUT ;
    USE SIGNAL ;
    SHAPE ABUTMENT ;
    PORT
      LAYER met2 ;
      RECT 1354.170 0.000 1354.310 0.420 ;
    END
  END rw0_rd_out[48]
  PIN rw0_rd_out[49]
    DIRECTION OUTPUT ;
    USE SIGNAL ;
    SHAPE ABUTMENT ;
    PORT
      LAYER met2 ;
      RECT 1366.130 0.000 1366.270 0.420 ;
    END
  END rw0_rd_out[49]
  PIN rw0_rd_out[50]
    DIRECTION OUTPUT ;
    USE SIGNAL ;
    SHAPE ABUTMENT ;
    PORT
      LAYER met2 ;
      RECT 1378.090 0.000 1378.230 0.420 ;
    END
  END rw0_rd_out[50]
  PIN rw0_rd_out[51]
    DIRECTION OUTPUT ;
    USE SIGNAL ;
    SHAPE ABUTMENT ;
    PORT
      LAYER met2 ;
      RECT 1390.050 0.000 1390.190 0.420 ;
    END
  END rw0_rd_out[51]
  PIN rw0_rd_out[52]
    DIRECTION OUTPUT ;
    USE SIGNAL ;
    SHAPE ABUTMENT ;
    PORT
      LAYER met2 ;
      RECT 1402.010 0.000 1402.150 0.420 ;
    END
  END rw0_rd_out[52]
  PIN rw0_rd_out[53]
    DIRECTION OUTPUT ;
    USE SIGNAL ;
    SHAPE ABUTMENT ;
    PORT
      LAYER met2 ;
      RECT 1413.970 0.000 1414.110 0.420 ;
    END
  END rw0_rd_out[53]
  PIN rw0_rd_out[54]
    DIRECTION OUTPUT ;
    USE SIGNAL ;
    SHAPE ABUTMENT ;
    PORT
      LAYER met2 ;
      RECT 1425.930 0.000 1426.070 0.420 ;
    END
  END rw0_rd_out[54]
  PIN rw0_rd_out[55]
    DIRECTION OUTPUT ;
    USE SIGNAL ;
    SHAPE ABUTMENT ;
    PORT
      LAYER met2 ;
      RECT 1437.890 0.000 1438.030 0.420 ;
    END
  END rw0_rd_out[55]
  PIN rw0_rd_out[56]
    DIRECTION OUTPUT ;
    USE SIGNAL ;
    SHAPE ABUTMENT ;
    PORT
      LAYER met2 ;
      RECT 1449.850 0.000 1449.990 0.420 ;
    END
  END rw0_rd_out[56]
  PIN rw0_rd_out[57]
    DIRECTION OUTPUT ;
    USE SIGNAL ;
    SHAPE ABUTMENT ;
    PORT
      LAYER met2 ;
      RECT 1461.810 0.000 1461.950 0.420 ;
    END
  END rw0_rd_out[57]
  PIN rw0_rd_out[58]
    DIRECTION OUTPUT ;
    USE SIGNAL ;
    SHAPE ABUTMENT ;
    PORT
      LAYER met2 ;
      RECT 1473.770 0.000 1473.910 0.420 ;
    END
  END rw0_rd_out[58]
  PIN rw0_rd_out[59]
    DIRECTION OUTPUT ;
    USE SIGNAL ;
    SHAPE ABUTMENT ;
    PORT
      LAYER met2 ;
      RECT 1485.730 0.000 1485.870 0.420 ;
    END
  END rw0_rd_out[59]
  PIN rw0_rd_out[60]
    DIRECTION OUTPUT ;
    USE SIGNAL ;
    SHAPE ABUTMENT ;
    PORT
      LAYER met2 ;
      RECT 1497.690 0.000 1497.830 0.420 ;
    END
  END rw0_rd_out[60]
  PIN rw0_rd_out[61]
    DIRECTION OUTPUT ;
    USE SIGNAL ;
    SHAPE ABUTMENT ;
    PORT
      LAYER met2 ;
      RECT 1509.650 0.000 1509.790 0.420 ;
    END
  END rw0_rd_out[61]
  PIN rw0_rd_out[62]
    DIRECTION OUTPUT ;
    USE SIGNAL ;
    SHAPE ABUTMENT ;
    PORT
      LAYER met2 ;
      RECT 1521.610 0.000 1521.750 0.420 ;
    END
  END rw0_rd_out[62]
  PIN rw0_rd_out[63]
    DIRECTION OUTPUT ;
    USE SIGNAL ;
    SHAPE ABUTMENT ;
    PORT
      LAYER met2 ;
      RECT 1533.570 0.000 1533.710 0.420 ;
    END
  END rw0_rd_out[63]
  PIN rw0_rd_out[64]
    DIRECTION OUTPUT ;
    USE SIGNAL ;
    SHAPE ABUTMENT ;
    PORT
      LAYER met2 ;
      RECT 1545.530 0.000 1545.670 0.420 ;
    END
  END rw0_rd_out[64]
  PIN rw0_rd_out[65]
    DIRECTION OUTPUT ;
    USE SIGNAL ;
    SHAPE ABUTMENT ;
    PORT
      LAYER met2 ;
      RECT 2.690 1895.420 2.830 1895.840 ;
    END
  END rw0_rd_out[65]
  PIN rw0_rd_out[66]
    DIRECTION OUTPUT ;
    USE SIGNAL ;
    SHAPE ABUTMENT ;
    PORT
      LAYER met2 ;
      RECT 19.710 1895.420 19.850 1895.840 ;
    END
  END rw0_rd_out[66]
  PIN rw0_rd_out[67]
    DIRECTION OUTPUT ;
    USE SIGNAL ;
    SHAPE ABUTMENT ;
    PORT
      LAYER met2 ;
      RECT 36.730 1895.420 36.870 1895.840 ;
    END
  END rw0_rd_out[67]
  PIN rw0_rd_out[68]
    DIRECTION OUTPUT ;
    USE SIGNAL ;
    SHAPE ABUTMENT ;
    PORT
      LAYER met2 ;
      RECT 53.750 1895.420 53.890 1895.840 ;
    END
  END rw0_rd_out[68]
  PIN rw0_rd_out[69]
    DIRECTION OUTPUT ;
    USE SIGNAL ;
    SHAPE ABUTMENT ;
    PORT
      LAYER met2 ;
      RECT 70.770 1895.420 70.910 1895.840 ;
    END
  END rw0_rd_out[69]
  PIN rw0_rd_out[70]
    DIRECTION OUTPUT ;
    USE SIGNAL ;
    SHAPE ABUTMENT ;
    PORT
      LAYER met2 ;
      RECT 87.790 1895.420 87.930 1895.840 ;
    END
  END rw0_rd_out[70]
  PIN rw0_rd_out[71]
    DIRECTION OUTPUT ;
    USE SIGNAL ;
    SHAPE ABUTMENT ;
    PORT
      LAYER met2 ;
      RECT 104.810 1895.420 104.950 1895.840 ;
    END
  END rw0_rd_out[71]
  PIN rw0_rd_out[72]
    DIRECTION OUTPUT ;
    USE SIGNAL ;
    SHAPE ABUTMENT ;
    PORT
      LAYER met2 ;
      RECT 121.830 1895.420 121.970 1895.840 ;
    END
  END rw0_rd_out[72]
  PIN rw0_rd_out[73]
    DIRECTION OUTPUT ;
    USE SIGNAL ;
    SHAPE ABUTMENT ;
    PORT
      LAYER met2 ;
      RECT 138.850 1895.420 138.990 1895.840 ;
    END
  END rw0_rd_out[73]
  PIN rw0_rd_out[74]
    DIRECTION OUTPUT ;
    USE SIGNAL ;
    SHAPE ABUTMENT ;
    PORT
      LAYER met2 ;
      RECT 155.870 1895.420 156.010 1895.840 ;
    END
  END rw0_rd_out[74]
  PIN rw0_rd_out[75]
    DIRECTION OUTPUT ;
    USE SIGNAL ;
    SHAPE ABUTMENT ;
    PORT
      LAYER met2 ;
      RECT 172.890 1895.420 173.030 1895.840 ;
    END
  END rw0_rd_out[75]
  PIN rw0_rd_out[76]
    DIRECTION OUTPUT ;
    USE SIGNAL ;
    SHAPE ABUTMENT ;
    PORT
      LAYER met2 ;
      RECT 189.910 1895.420 190.050 1895.840 ;
    END
  END rw0_rd_out[76]
  PIN rw0_rd_out[77]
    DIRECTION OUTPUT ;
    USE SIGNAL ;
    SHAPE ABUTMENT ;
    PORT
      LAYER met2 ;
      RECT 206.930 1895.420 207.070 1895.840 ;
    END
  END rw0_rd_out[77]
  PIN rw0_rd_out[78]
    DIRECTION OUTPUT ;
    USE SIGNAL ;
    SHAPE ABUTMENT ;
    PORT
      LAYER met2 ;
      RECT 223.950 1895.420 224.090 1895.840 ;
    END
  END rw0_rd_out[78]
  PIN rw0_rd_out[79]
    DIRECTION OUTPUT ;
    USE SIGNAL ;
    SHAPE ABUTMENT ;
    PORT
      LAYER met2 ;
      RECT 240.970 1895.420 241.110 1895.840 ;
    END
  END rw0_rd_out[79]
  PIN rw0_rd_out[80]
    DIRECTION OUTPUT ;
    USE SIGNAL ;
    SHAPE ABUTMENT ;
    PORT
      LAYER met2 ;
      RECT 257.990 1895.420 258.130 1895.840 ;
    END
  END rw0_rd_out[80]
  PIN rw0_rd_out[81]
    DIRECTION OUTPUT ;
    USE SIGNAL ;
    SHAPE ABUTMENT ;
    PORT
      LAYER met2 ;
      RECT 275.010 1895.420 275.150 1895.840 ;
    END
  END rw0_rd_out[81]
  PIN rw0_rd_out[82]
    DIRECTION OUTPUT ;
    USE SIGNAL ;
    SHAPE ABUTMENT ;
    PORT
      LAYER met2 ;
      RECT 292.030 1895.420 292.170 1895.840 ;
    END
  END rw0_rd_out[82]
  PIN rw0_rd_out[83]
    DIRECTION OUTPUT ;
    USE SIGNAL ;
    SHAPE ABUTMENT ;
    PORT
      LAYER met2 ;
      RECT 309.050 1895.420 309.190 1895.840 ;
    END
  END rw0_rd_out[83]
  PIN rw0_rd_out[84]
    DIRECTION OUTPUT ;
    USE SIGNAL ;
    SHAPE ABUTMENT ;
    PORT
      LAYER met2 ;
      RECT 326.070 1895.420 326.210 1895.840 ;
    END
  END rw0_rd_out[84]
  PIN rw0_rd_out[85]
    DIRECTION OUTPUT ;
    USE SIGNAL ;
    SHAPE ABUTMENT ;
    PORT
      LAYER met2 ;
      RECT 343.090 1895.420 343.230 1895.840 ;
    END
  END rw0_rd_out[85]
  PIN rw0_rd_out[86]
    DIRECTION OUTPUT ;
    USE SIGNAL ;
    SHAPE ABUTMENT ;
    PORT
      LAYER met2 ;
      RECT 360.110 1895.420 360.250 1895.840 ;
    END
  END rw0_rd_out[86]
  PIN rw0_rd_out[87]
    DIRECTION OUTPUT ;
    USE SIGNAL ;
    SHAPE ABUTMENT ;
    PORT
      LAYER met2 ;
      RECT 377.130 1895.420 377.270 1895.840 ;
    END
  END rw0_rd_out[87]
  PIN rw0_rd_out[88]
    DIRECTION OUTPUT ;
    USE SIGNAL ;
    SHAPE ABUTMENT ;
    PORT
      LAYER met2 ;
      RECT 394.150 1895.420 394.290 1895.840 ;
    END
  END rw0_rd_out[88]
  PIN rw0_rd_out[89]
    DIRECTION OUTPUT ;
    USE SIGNAL ;
    SHAPE ABUTMENT ;
    PORT
      LAYER met2 ;
      RECT 411.170 1895.420 411.310 1895.840 ;
    END
  END rw0_rd_out[89]
  PIN rw0_rd_out[90]
    DIRECTION OUTPUT ;
    USE SIGNAL ;
    SHAPE ABUTMENT ;
    PORT
      LAYER met2 ;
      RECT 428.190 1895.420 428.330 1895.840 ;
    END
  END rw0_rd_out[90]
  PIN rw0_rd_out[91]
    DIRECTION OUTPUT ;
    USE SIGNAL ;
    SHAPE ABUTMENT ;
    PORT
      LAYER met2 ;
      RECT 445.210 1895.420 445.350 1895.840 ;
    END
  END rw0_rd_out[91]
  PIN rw0_rd_out[92]
    DIRECTION OUTPUT ;
    USE SIGNAL ;
    SHAPE ABUTMENT ;
    PORT
      LAYER met2 ;
      RECT 462.230 1895.420 462.370 1895.840 ;
    END
  END rw0_rd_out[92]
  PIN rw0_rd_out[93]
    DIRECTION OUTPUT ;
    USE SIGNAL ;
    SHAPE ABUTMENT ;
    PORT
      LAYER met2 ;
      RECT 479.250 1895.420 479.390 1895.840 ;
    END
  END rw0_rd_out[93]
  PIN rw0_rd_out[94]
    DIRECTION OUTPUT ;
    USE SIGNAL ;
    SHAPE ABUTMENT ;
    PORT
      LAYER met2 ;
      RECT 496.270 1895.420 496.410 1895.840 ;
    END
  END rw0_rd_out[94]
  PIN rw0_rd_out[95]
    DIRECTION OUTPUT ;
    USE SIGNAL ;
    SHAPE ABUTMENT ;
    PORT
      LAYER met2 ;
      RECT 513.290 1895.420 513.430 1895.840 ;
    END
  END rw0_rd_out[95]
  PIN rw0_rd_out[96]
    DIRECTION OUTPUT ;
    USE SIGNAL ;
    SHAPE ABUTMENT ;
    PORT
      LAYER met2 ;
      RECT 530.310 1895.420 530.450 1895.840 ;
    END
  END rw0_rd_out[96]
  PIN rw0_rd_out[97]
    DIRECTION OUTPUT ;
    USE SIGNAL ;
    SHAPE ABUTMENT ;
    PORT
      LAYER met2 ;
      RECT 547.330 1895.420 547.470 1895.840 ;
    END
  END rw0_rd_out[97]
  PIN rw0_rd_out[98]
    DIRECTION OUTPUT ;
    USE SIGNAL ;
    SHAPE ABUTMENT ;
    PORT
      LAYER met2 ;
      RECT 564.350 1895.420 564.490 1895.840 ;
    END
  END rw0_rd_out[98]
  PIN rw0_rd_out[99]
    DIRECTION OUTPUT ;
    USE SIGNAL ;
    SHAPE ABUTMENT ;
    PORT
      LAYER met2 ;
      RECT 581.370 1895.420 581.510 1895.840 ;
    END
  END rw0_rd_out[99]
  PIN rw0_rd_out[100]
    DIRECTION OUTPUT ;
    USE SIGNAL ;
    SHAPE ABUTMENT ;
    PORT
      LAYER met2 ;
      RECT 598.390 1895.420 598.530 1895.840 ;
    END
  END rw0_rd_out[100]
  PIN rw0_rd_out[101]
    DIRECTION OUTPUT ;
    USE SIGNAL ;
    SHAPE ABUTMENT ;
    PORT
      LAYER met2 ;
      RECT 615.410 1895.420 615.550 1895.840 ;
    END
  END rw0_rd_out[101]
  PIN rw0_rd_out[102]
    DIRECTION OUTPUT ;
    USE SIGNAL ;
    SHAPE ABUTMENT ;
    PORT
      LAYER met2 ;
      RECT 632.430 1895.420 632.570 1895.840 ;
    END
  END rw0_rd_out[102]
  PIN rw0_rd_out[103]
    DIRECTION OUTPUT ;
    USE SIGNAL ;
    SHAPE ABUTMENT ;
    PORT
      LAYER met2 ;
      RECT 649.450 1895.420 649.590 1895.840 ;
    END
  END rw0_rd_out[103]
  PIN rw0_rd_out[104]
    DIRECTION OUTPUT ;
    USE SIGNAL ;
    SHAPE ABUTMENT ;
    PORT
      LAYER met2 ;
      RECT 666.470 1895.420 666.610 1895.840 ;
    END
  END rw0_rd_out[104]
  PIN rw0_rd_out[105]
    DIRECTION OUTPUT ;
    USE SIGNAL ;
    SHAPE ABUTMENT ;
    PORT
      LAYER met2 ;
      RECT 683.490 1895.420 683.630 1895.840 ;
    END
  END rw0_rd_out[105]
  PIN rw0_rd_out[106]
    DIRECTION OUTPUT ;
    USE SIGNAL ;
    SHAPE ABUTMENT ;
    PORT
      LAYER met2 ;
      RECT 700.510 1895.420 700.650 1895.840 ;
    END
  END rw0_rd_out[106]
  PIN rw0_rd_out[107]
    DIRECTION OUTPUT ;
    USE SIGNAL ;
    SHAPE ABUTMENT ;
    PORT
      LAYER met2 ;
      RECT 717.530 1895.420 717.670 1895.840 ;
    END
  END rw0_rd_out[107]
  PIN rw0_rd_out[108]
    DIRECTION OUTPUT ;
    USE SIGNAL ;
    SHAPE ABUTMENT ;
    PORT
      LAYER met2 ;
      RECT 734.550 1895.420 734.690 1895.840 ;
    END
  END rw0_rd_out[108]
  PIN rw0_rd_out[109]
    DIRECTION OUTPUT ;
    USE SIGNAL ;
    SHAPE ABUTMENT ;
    PORT
      LAYER met2 ;
      RECT 751.570 1895.420 751.710 1895.840 ;
    END
  END rw0_rd_out[109]
  PIN rw0_rd_out[110]
    DIRECTION OUTPUT ;
    USE SIGNAL ;
    SHAPE ABUTMENT ;
    PORT
      LAYER met2 ;
      RECT 768.590 1895.420 768.730 1895.840 ;
    END
  END rw0_rd_out[110]
  PIN rw0_rd_out[111]
    DIRECTION OUTPUT ;
    USE SIGNAL ;
    SHAPE ABUTMENT ;
    PORT
      LAYER met2 ;
      RECT 785.610 1895.420 785.750 1895.840 ;
    END
  END rw0_rd_out[111]
  PIN rw0_rd_out[112]
    DIRECTION OUTPUT ;
    USE SIGNAL ;
    SHAPE ABUTMENT ;
    PORT
      LAYER met2 ;
      RECT 802.630 1895.420 802.770 1895.840 ;
    END
  END rw0_rd_out[112]
  PIN rw0_rd_out[113]
    DIRECTION OUTPUT ;
    USE SIGNAL ;
    SHAPE ABUTMENT ;
    PORT
      LAYER met2 ;
      RECT 819.650 1895.420 819.790 1895.840 ;
    END
  END rw0_rd_out[113]
  PIN rw0_rd_out[114]
    DIRECTION OUTPUT ;
    USE SIGNAL ;
    SHAPE ABUTMENT ;
    PORT
      LAYER met2 ;
      RECT 836.670 1895.420 836.810 1895.840 ;
    END
  END rw0_rd_out[114]
  PIN rw0_rd_out[115]
    DIRECTION OUTPUT ;
    USE SIGNAL ;
    SHAPE ABUTMENT ;
    PORT
      LAYER met2 ;
      RECT 853.690 1895.420 853.830 1895.840 ;
    END
  END rw0_rd_out[115]
  PIN rw0_rd_out[116]
    DIRECTION OUTPUT ;
    USE SIGNAL ;
    SHAPE ABUTMENT ;
    PORT
      LAYER met2 ;
      RECT 870.710 1895.420 870.850 1895.840 ;
    END
  END rw0_rd_out[116]
  PIN rw0_rd_out[117]
    DIRECTION OUTPUT ;
    USE SIGNAL ;
    SHAPE ABUTMENT ;
    PORT
      LAYER met2 ;
      RECT 887.730 1895.420 887.870 1895.840 ;
    END
  END rw0_rd_out[117]
  PIN rw0_rd_out[118]
    DIRECTION OUTPUT ;
    USE SIGNAL ;
    SHAPE ABUTMENT ;
    PORT
      LAYER met2 ;
      RECT 904.750 1895.420 904.890 1895.840 ;
    END
  END rw0_rd_out[118]
  PIN rw0_rd_out[119]
    DIRECTION OUTPUT ;
    USE SIGNAL ;
    SHAPE ABUTMENT ;
    PORT
      LAYER met2 ;
      RECT 921.770 1895.420 921.910 1895.840 ;
    END
  END rw0_rd_out[119]
  PIN rw0_rd_out[120]
    DIRECTION OUTPUT ;
    USE SIGNAL ;
    SHAPE ABUTMENT ;
    PORT
      LAYER met2 ;
      RECT 938.790 1895.420 938.930 1895.840 ;
    END
  END rw0_rd_out[120]
  PIN rw0_rd_out[121]
    DIRECTION OUTPUT ;
    USE SIGNAL ;
    SHAPE ABUTMENT ;
    PORT
      LAYER met2 ;
      RECT 955.810 1895.420 955.950 1895.840 ;
    END
  END rw0_rd_out[121]
  PIN rw0_rd_out[122]
    DIRECTION OUTPUT ;
    USE SIGNAL ;
    SHAPE ABUTMENT ;
    PORT
      LAYER met2 ;
      RECT 972.830 1895.420 972.970 1895.840 ;
    END
  END rw0_rd_out[122]
  PIN rw0_rd_out[123]
    DIRECTION OUTPUT ;
    USE SIGNAL ;
    SHAPE ABUTMENT ;
    PORT
      LAYER met2 ;
      RECT 989.850 1895.420 989.990 1895.840 ;
    END
  END rw0_rd_out[123]
  PIN rw0_rd_out[124]
    DIRECTION OUTPUT ;
    USE SIGNAL ;
    SHAPE ABUTMENT ;
    PORT
      LAYER met2 ;
      RECT 1006.870 1895.420 1007.010 1895.840 ;
    END
  END rw0_rd_out[124]
  PIN rw0_rd_out[125]
    DIRECTION OUTPUT ;
    USE SIGNAL ;
    SHAPE ABUTMENT ;
    PORT
      LAYER met2 ;
      RECT 1023.890 1895.420 1024.030 1895.840 ;
    END
  END rw0_rd_out[125]
  PIN rw0_rd_out[126]
    DIRECTION OUTPUT ;
    USE SIGNAL ;
    SHAPE ABUTMENT ;
    PORT
      LAYER met2 ;
      RECT 1040.910 1895.420 1041.050 1895.840 ;
    END
  END rw0_rd_out[126]
  PIN rw0_rd_out[127]
    DIRECTION OUTPUT ;
    USE SIGNAL ;
    SHAPE ABUTMENT ;
    PORT
      LAYER met2 ;
      RECT 1057.930 1895.420 1058.070 1895.840 ;
    END
  END rw0_rd_out[127]
  PIN rw0_rd_out[128]
    DIRECTION OUTPUT ;
    USE SIGNAL ;
    SHAPE ABUTMENT ;
    PORT
      LAYER met2 ;
      RECT 1074.950 1895.420 1075.090 1895.840 ;
    END
  END rw0_rd_out[128]
  PIN rw0_rd_out[129]
    DIRECTION OUTPUT ;
    USE SIGNAL ;
    SHAPE ABUTMENT ;
    PORT
      LAYER met2 ;
      RECT 1091.970 1895.420 1092.110 1895.840 ;
    END
  END rw0_rd_out[129]
  PIN r0_rd_out[0]
    DIRECTION OUTPUT ;
    USE SIGNAL ;
    SHAPE ABUTMENT ;
    PORT
      LAYER met2 ;
      RECT 1557.490 0.000 1557.630 0.420 ;
    END
  END r0_rd_out[0]
  PIN r0_rd_out[1]
    DIRECTION OUTPUT ;
    USE SIGNAL ;
    SHAPE ABUTMENT ;
    PORT
      LAYER met2 ;
      RECT 1569.450 0.000 1569.590 0.420 ;
    END
  END r0_rd_out[1]
  PIN r0_rd_out[2]
    DIRECTION OUTPUT ;
    USE SIGNAL ;
    SHAPE ABUTMENT ;
    PORT
      LAYER met2 ;
      RECT 1581.410 0.000 1581.550 0.420 ;
    END
  END r0_rd_out[2]
  PIN r0_rd_out[3]
    DIRECTION OUTPUT ;
    USE SIGNAL ;
    SHAPE ABUTMENT ;
    PORT
      LAYER met2 ;
      RECT 1593.370 0.000 1593.510 0.420 ;
    END
  END r0_rd_out[3]
  PIN r0_rd_out[4]
    DIRECTION OUTPUT ;
    USE SIGNAL ;
    SHAPE ABUTMENT ;
    PORT
      LAYER met2 ;
      RECT 1605.330 0.000 1605.470 0.420 ;
    END
  END r0_rd_out[4]
  PIN r0_rd_out[5]
    DIRECTION OUTPUT ;
    USE SIGNAL ;
    SHAPE ABUTMENT ;
    PORT
      LAYER met2 ;
      RECT 1617.290 0.000 1617.430 0.420 ;
    END
  END r0_rd_out[5]
  PIN r0_rd_out[6]
    DIRECTION OUTPUT ;
    USE SIGNAL ;
    SHAPE ABUTMENT ;
    PORT
      LAYER met2 ;
      RECT 1629.250 0.000 1629.390 0.420 ;
    END
  END r0_rd_out[6]
  PIN r0_rd_out[7]
    DIRECTION OUTPUT ;
    USE SIGNAL ;
    SHAPE ABUTMENT ;
    PORT
      LAYER met2 ;
      RECT 1641.210 0.000 1641.350 0.420 ;
    END
  END r0_rd_out[7]
  PIN r0_rd_out[8]
    DIRECTION OUTPUT ;
    USE SIGNAL ;
    SHAPE ABUTMENT ;
    PORT
      LAYER met2 ;
      RECT 1653.170 0.000 1653.310 0.420 ;
    END
  END r0_rd_out[8]
  PIN r0_rd_out[9]
    DIRECTION OUTPUT ;
    USE SIGNAL ;
    SHAPE ABUTMENT ;
    PORT
      LAYER met2 ;
      RECT 1665.130 0.000 1665.270 0.420 ;
    END
  END r0_rd_out[9]
  PIN r0_rd_out[10]
    DIRECTION OUTPUT ;
    USE SIGNAL ;
    SHAPE ABUTMENT ;
    PORT
      LAYER met2 ;
      RECT 1677.090 0.000 1677.230 0.420 ;
    END
  END r0_rd_out[10]
  PIN r0_rd_out[11]
    DIRECTION OUTPUT ;
    USE SIGNAL ;
    SHAPE ABUTMENT ;
    PORT
      LAYER met2 ;
      RECT 1689.050 0.000 1689.190 0.420 ;
    END
  END r0_rd_out[11]
  PIN r0_rd_out[12]
    DIRECTION OUTPUT ;
    USE SIGNAL ;
    SHAPE ABUTMENT ;
    PORT
      LAYER met2 ;
      RECT 1701.010 0.000 1701.150 0.420 ;
    END
  END r0_rd_out[12]
  PIN r0_rd_out[13]
    DIRECTION OUTPUT ;
    USE SIGNAL ;
    SHAPE ABUTMENT ;
    PORT
      LAYER met2 ;
      RECT 1712.970 0.000 1713.110 0.420 ;
    END
  END r0_rd_out[13]
  PIN r0_rd_out[14]
    DIRECTION OUTPUT ;
    USE SIGNAL ;
    SHAPE ABUTMENT ;
    PORT
      LAYER met2 ;
      RECT 1724.930 0.000 1725.070 0.420 ;
    END
  END r0_rd_out[14]
  PIN r0_rd_out[15]
    DIRECTION OUTPUT ;
    USE SIGNAL ;
    SHAPE ABUTMENT ;
    PORT
      LAYER met2 ;
      RECT 1736.890 0.000 1737.030 0.420 ;
    END
  END r0_rd_out[15]
  PIN r0_rd_out[16]
    DIRECTION OUTPUT ;
    USE SIGNAL ;
    SHAPE ABUTMENT ;
    PORT
      LAYER met2 ;
      RECT 1748.850 0.000 1748.990 0.420 ;
    END
  END r0_rd_out[16]
  PIN r0_rd_out[17]
    DIRECTION OUTPUT ;
    USE SIGNAL ;
    SHAPE ABUTMENT ;
    PORT
      LAYER met2 ;
      RECT 1760.810 0.000 1760.950 0.420 ;
    END
  END r0_rd_out[17]
  PIN r0_rd_out[18]
    DIRECTION OUTPUT ;
    USE SIGNAL ;
    SHAPE ABUTMENT ;
    PORT
      LAYER met2 ;
      RECT 1772.770 0.000 1772.910 0.420 ;
    END
  END r0_rd_out[18]
  PIN r0_rd_out[19]
    DIRECTION OUTPUT ;
    USE SIGNAL ;
    SHAPE ABUTMENT ;
    PORT
      LAYER met2 ;
      RECT 1784.730 0.000 1784.870 0.420 ;
    END
  END r0_rd_out[19]
  PIN r0_rd_out[20]
    DIRECTION OUTPUT ;
    USE SIGNAL ;
    SHAPE ABUTMENT ;
    PORT
      LAYER met2 ;
      RECT 1796.690 0.000 1796.830 0.420 ;
    END
  END r0_rd_out[20]
  PIN r0_rd_out[21]
    DIRECTION OUTPUT ;
    USE SIGNAL ;
    SHAPE ABUTMENT ;
    PORT
      LAYER met2 ;
      RECT 1808.650 0.000 1808.790 0.420 ;
    END
  END r0_rd_out[21]
  PIN r0_rd_out[22]
    DIRECTION OUTPUT ;
    USE SIGNAL ;
    SHAPE ABUTMENT ;
    PORT
      LAYER met2 ;
      RECT 1820.610 0.000 1820.750 0.420 ;
    END
  END r0_rd_out[22]
  PIN r0_rd_out[23]
    DIRECTION OUTPUT ;
    USE SIGNAL ;
    SHAPE ABUTMENT ;
    PORT
      LAYER met2 ;
      RECT 1832.570 0.000 1832.710 0.420 ;
    END
  END r0_rd_out[23]
  PIN r0_rd_out[24]
    DIRECTION OUTPUT ;
    USE SIGNAL ;
    SHAPE ABUTMENT ;
    PORT
      LAYER met2 ;
      RECT 1844.530 0.000 1844.670 0.420 ;
    END
  END r0_rd_out[24]
  PIN r0_rd_out[25]
    DIRECTION OUTPUT ;
    USE SIGNAL ;
    SHAPE ABUTMENT ;
    PORT
      LAYER met2 ;
      RECT 1856.490 0.000 1856.630 0.420 ;
    END
  END r0_rd_out[25]
  PIN r0_rd_out[26]
    DIRECTION OUTPUT ;
    USE SIGNAL ;
    SHAPE ABUTMENT ;
    PORT
      LAYER met2 ;
      RECT 1868.450 0.000 1868.590 0.420 ;
    END
  END r0_rd_out[26]
  PIN r0_rd_out[27]
    DIRECTION OUTPUT ;
    USE SIGNAL ;
    SHAPE ABUTMENT ;
    PORT
      LAYER met2 ;
      RECT 1880.410 0.000 1880.550 0.420 ;
    END
  END r0_rd_out[27]
  PIN r0_rd_out[28]
    DIRECTION OUTPUT ;
    USE SIGNAL ;
    SHAPE ABUTMENT ;
    PORT
      LAYER met2 ;
      RECT 1892.370 0.000 1892.510 0.420 ;
    END
  END r0_rd_out[28]
  PIN r0_rd_out[29]
    DIRECTION OUTPUT ;
    USE SIGNAL ;
    SHAPE ABUTMENT ;
    PORT
      LAYER met2 ;
      RECT 1904.330 0.000 1904.470 0.420 ;
    END
  END r0_rd_out[29]
  PIN r0_rd_out[30]
    DIRECTION OUTPUT ;
    USE SIGNAL ;
    SHAPE ABUTMENT ;
    PORT
      LAYER met2 ;
      RECT 1916.290 0.000 1916.430 0.420 ;
    END
  END r0_rd_out[30]
  PIN r0_rd_out[31]
    DIRECTION OUTPUT ;
    USE SIGNAL ;
    SHAPE ABUTMENT ;
    PORT
      LAYER met2 ;
      RECT 1928.250 0.000 1928.390 0.420 ;
    END
  END r0_rd_out[31]
  PIN r0_rd_out[32]
    DIRECTION OUTPUT ;
    USE SIGNAL ;
    SHAPE ABUTMENT ;
    PORT
      LAYER met2 ;
      RECT 1940.210 0.000 1940.350 0.420 ;
    END
  END r0_rd_out[32]
  PIN r0_rd_out[33]
    DIRECTION OUTPUT ;
    USE SIGNAL ;
    SHAPE ABUTMENT ;
    PORT
      LAYER met2 ;
      RECT 1952.170 0.000 1952.310 0.420 ;
    END
  END r0_rd_out[33]
  PIN r0_rd_out[34]
    DIRECTION OUTPUT ;
    USE SIGNAL ;
    SHAPE ABUTMENT ;
    PORT
      LAYER met2 ;
      RECT 1964.130 0.000 1964.270 0.420 ;
    END
  END r0_rd_out[34]
  PIN r0_rd_out[35]
    DIRECTION OUTPUT ;
    USE SIGNAL ;
    SHAPE ABUTMENT ;
    PORT
      LAYER met2 ;
      RECT 1976.090 0.000 1976.230 0.420 ;
    END
  END r0_rd_out[35]
  PIN r0_rd_out[36]
    DIRECTION OUTPUT ;
    USE SIGNAL ;
    SHAPE ABUTMENT ;
    PORT
      LAYER met2 ;
      RECT 1988.050 0.000 1988.190 0.420 ;
    END
  END r0_rd_out[36]
  PIN r0_rd_out[37]
    DIRECTION OUTPUT ;
    USE SIGNAL ;
    SHAPE ABUTMENT ;
    PORT
      LAYER met2 ;
      RECT 2000.010 0.000 2000.150 0.420 ;
    END
  END r0_rd_out[37]
  PIN r0_rd_out[38]
    DIRECTION OUTPUT ;
    USE SIGNAL ;
    SHAPE ABUTMENT ;
    PORT
      LAYER met2 ;
      RECT 2011.970 0.000 2012.110 0.420 ;
    END
  END r0_rd_out[38]
  PIN r0_rd_out[39]
    DIRECTION OUTPUT ;
    USE SIGNAL ;
    SHAPE ABUTMENT ;
    PORT
      LAYER met2 ;
      RECT 2023.930 0.000 2024.070 0.420 ;
    END
  END r0_rd_out[39]
  PIN r0_rd_out[40]
    DIRECTION OUTPUT ;
    USE SIGNAL ;
    SHAPE ABUTMENT ;
    PORT
      LAYER met2 ;
      RECT 2035.890 0.000 2036.030 0.420 ;
    END
  END r0_rd_out[40]
  PIN r0_rd_out[41]
    DIRECTION OUTPUT ;
    USE SIGNAL ;
    SHAPE ABUTMENT ;
    PORT
      LAYER met2 ;
      RECT 2047.850 0.000 2047.990 0.420 ;
    END
  END r0_rd_out[41]
  PIN r0_rd_out[42]
    DIRECTION OUTPUT ;
    USE SIGNAL ;
    SHAPE ABUTMENT ;
    PORT
      LAYER met2 ;
      RECT 2059.810 0.000 2059.950 0.420 ;
    END
  END r0_rd_out[42]
  PIN r0_rd_out[43]
    DIRECTION OUTPUT ;
    USE SIGNAL ;
    SHAPE ABUTMENT ;
    PORT
      LAYER met2 ;
      RECT 2071.770 0.000 2071.910 0.420 ;
    END
  END r0_rd_out[43]
  PIN r0_rd_out[44]
    DIRECTION OUTPUT ;
    USE SIGNAL ;
    SHAPE ABUTMENT ;
    PORT
      LAYER met2 ;
      RECT 2083.730 0.000 2083.870 0.420 ;
    END
  END r0_rd_out[44]
  PIN r0_rd_out[45]
    DIRECTION OUTPUT ;
    USE SIGNAL ;
    SHAPE ABUTMENT ;
    PORT
      LAYER met2 ;
      RECT 2095.690 0.000 2095.830 0.420 ;
    END
  END r0_rd_out[45]
  PIN r0_rd_out[46]
    DIRECTION OUTPUT ;
    USE SIGNAL ;
    SHAPE ABUTMENT ;
    PORT
      LAYER met2 ;
      RECT 2107.650 0.000 2107.790 0.420 ;
    END
  END r0_rd_out[46]
  PIN r0_rd_out[47]
    DIRECTION OUTPUT ;
    USE SIGNAL ;
    SHAPE ABUTMENT ;
    PORT
      LAYER met2 ;
      RECT 2119.610 0.000 2119.750 0.420 ;
    END
  END r0_rd_out[47]
  PIN r0_rd_out[48]
    DIRECTION OUTPUT ;
    USE SIGNAL ;
    SHAPE ABUTMENT ;
    PORT
      LAYER met2 ;
      RECT 2131.570 0.000 2131.710 0.420 ;
    END
  END r0_rd_out[48]
  PIN r0_rd_out[49]
    DIRECTION OUTPUT ;
    USE SIGNAL ;
    SHAPE ABUTMENT ;
    PORT
      LAYER met2 ;
      RECT 2143.530 0.000 2143.670 0.420 ;
    END
  END r0_rd_out[49]
  PIN r0_rd_out[50]
    DIRECTION OUTPUT ;
    USE SIGNAL ;
    SHAPE ABUTMENT ;
    PORT
      LAYER met2 ;
      RECT 2155.490 0.000 2155.630 0.420 ;
    END
  END r0_rd_out[50]
  PIN r0_rd_out[51]
    DIRECTION OUTPUT ;
    USE SIGNAL ;
    SHAPE ABUTMENT ;
    PORT
      LAYER met2 ;
      RECT 2167.450 0.000 2167.590 0.420 ;
    END
  END r0_rd_out[51]
  PIN r0_rd_out[52]
    DIRECTION OUTPUT ;
    USE SIGNAL ;
    SHAPE ABUTMENT ;
    PORT
      LAYER met2 ;
      RECT 2179.410 0.000 2179.550 0.420 ;
    END
  END r0_rd_out[52]
  PIN r0_rd_out[53]
    DIRECTION OUTPUT ;
    USE SIGNAL ;
    SHAPE ABUTMENT ;
    PORT
      LAYER met2 ;
      RECT 2191.370 0.000 2191.510 0.420 ;
    END
  END r0_rd_out[53]
  PIN r0_rd_out[54]
    DIRECTION OUTPUT ;
    USE SIGNAL ;
    SHAPE ABUTMENT ;
    PORT
      LAYER met2 ;
      RECT 2203.330 0.000 2203.470 0.420 ;
    END
  END r0_rd_out[54]
  PIN r0_rd_out[55]
    DIRECTION OUTPUT ;
    USE SIGNAL ;
    SHAPE ABUTMENT ;
    PORT
      LAYER met2 ;
      RECT 2215.290 0.000 2215.430 0.420 ;
    END
  END r0_rd_out[55]
  PIN r0_rd_out[56]
    DIRECTION OUTPUT ;
    USE SIGNAL ;
    SHAPE ABUTMENT ;
    PORT
      LAYER met2 ;
      RECT 2227.250 0.000 2227.390 0.420 ;
    END
  END r0_rd_out[56]
  PIN r0_rd_out[57]
    DIRECTION OUTPUT ;
    USE SIGNAL ;
    SHAPE ABUTMENT ;
    PORT
      LAYER met2 ;
      RECT 2239.210 0.000 2239.350 0.420 ;
    END
  END r0_rd_out[57]
  PIN r0_rd_out[58]
    DIRECTION OUTPUT ;
    USE SIGNAL ;
    SHAPE ABUTMENT ;
    PORT
      LAYER met2 ;
      RECT 2251.170 0.000 2251.310 0.420 ;
    END
  END r0_rd_out[58]
  PIN r0_rd_out[59]
    DIRECTION OUTPUT ;
    USE SIGNAL ;
    SHAPE ABUTMENT ;
    PORT
      LAYER met2 ;
      RECT 2263.130 0.000 2263.270 0.420 ;
    END
  END r0_rd_out[59]
  PIN r0_rd_out[60]
    DIRECTION OUTPUT ;
    USE SIGNAL ;
    SHAPE ABUTMENT ;
    PORT
      LAYER met2 ;
      RECT 2275.090 0.000 2275.230 0.420 ;
    END
  END r0_rd_out[60]
  PIN r0_rd_out[61]
    DIRECTION OUTPUT ;
    USE SIGNAL ;
    SHAPE ABUTMENT ;
    PORT
      LAYER met2 ;
      RECT 2287.050 0.000 2287.190 0.420 ;
    END
  END r0_rd_out[61]
  PIN r0_rd_out[62]
    DIRECTION OUTPUT ;
    USE SIGNAL ;
    SHAPE ABUTMENT ;
    PORT
      LAYER met2 ;
      RECT 2299.010 0.000 2299.150 0.420 ;
    END
  END r0_rd_out[62]
  PIN r0_rd_out[63]
    DIRECTION OUTPUT ;
    USE SIGNAL ;
    SHAPE ABUTMENT ;
    PORT
      LAYER met2 ;
      RECT 2310.970 0.000 2311.110 0.420 ;
    END
  END r0_rd_out[63]
  PIN r0_rd_out[64]
    DIRECTION OUTPUT ;
    USE SIGNAL ;
    SHAPE ABUTMENT ;
    PORT
      LAYER met2 ;
      RECT 2322.930 0.000 2323.070 0.420 ;
    END
  END r0_rd_out[64]
  PIN r0_rd_out[65]
    DIRECTION OUTPUT ;
    USE SIGNAL ;
    SHAPE ABUTMENT ;
    PORT
      LAYER met2 ;
      RECT 1108.990 1895.420 1109.130 1895.840 ;
    END
  END r0_rd_out[65]
  PIN r0_rd_out[66]
    DIRECTION OUTPUT ;
    USE SIGNAL ;
    SHAPE ABUTMENT ;
    PORT
      LAYER met2 ;
      RECT 1126.010 1895.420 1126.150 1895.840 ;
    END
  END r0_rd_out[66]
  PIN r0_rd_out[67]
    DIRECTION OUTPUT ;
    USE SIGNAL ;
    SHAPE ABUTMENT ;
    PORT
      LAYER met2 ;
      RECT 1143.030 1895.420 1143.170 1895.840 ;
    END
  END r0_rd_out[67]
  PIN r0_rd_out[68]
    DIRECTION OUTPUT ;
    USE SIGNAL ;
    SHAPE ABUTMENT ;
    PORT
      LAYER met2 ;
      RECT 1160.050 1895.420 1160.190 1895.840 ;
    END
  END r0_rd_out[68]
  PIN r0_rd_out[69]
    DIRECTION OUTPUT ;
    USE SIGNAL ;
    SHAPE ABUTMENT ;
    PORT
      LAYER met2 ;
      RECT 1177.070 1895.420 1177.210 1895.840 ;
    END
  END r0_rd_out[69]
  PIN r0_rd_out[70]
    DIRECTION OUTPUT ;
    USE SIGNAL ;
    SHAPE ABUTMENT ;
    PORT
      LAYER met2 ;
      RECT 1194.090 1895.420 1194.230 1895.840 ;
    END
  END r0_rd_out[70]
  PIN r0_rd_out[71]
    DIRECTION OUTPUT ;
    USE SIGNAL ;
    SHAPE ABUTMENT ;
    PORT
      LAYER met2 ;
      RECT 1211.110 1895.420 1211.250 1895.840 ;
    END
  END r0_rd_out[71]
  PIN r0_rd_out[72]
    DIRECTION OUTPUT ;
    USE SIGNAL ;
    SHAPE ABUTMENT ;
    PORT
      LAYER met2 ;
      RECT 1228.130 1895.420 1228.270 1895.840 ;
    END
  END r0_rd_out[72]
  PIN r0_rd_out[73]
    DIRECTION OUTPUT ;
    USE SIGNAL ;
    SHAPE ABUTMENT ;
    PORT
      LAYER met2 ;
      RECT 1245.150 1895.420 1245.290 1895.840 ;
    END
  END r0_rd_out[73]
  PIN r0_rd_out[74]
    DIRECTION OUTPUT ;
    USE SIGNAL ;
    SHAPE ABUTMENT ;
    PORT
      LAYER met2 ;
      RECT 1262.170 1895.420 1262.310 1895.840 ;
    END
  END r0_rd_out[74]
  PIN r0_rd_out[75]
    DIRECTION OUTPUT ;
    USE SIGNAL ;
    SHAPE ABUTMENT ;
    PORT
      LAYER met2 ;
      RECT 1279.190 1895.420 1279.330 1895.840 ;
    END
  END r0_rd_out[75]
  PIN r0_rd_out[76]
    DIRECTION OUTPUT ;
    USE SIGNAL ;
    SHAPE ABUTMENT ;
    PORT
      LAYER met2 ;
      RECT 1296.210 1895.420 1296.350 1895.840 ;
    END
  END r0_rd_out[76]
  PIN r0_rd_out[77]
    DIRECTION OUTPUT ;
    USE SIGNAL ;
    SHAPE ABUTMENT ;
    PORT
      LAYER met2 ;
      RECT 1313.230 1895.420 1313.370 1895.840 ;
    END
  END r0_rd_out[77]
  PIN r0_rd_out[78]
    DIRECTION OUTPUT ;
    USE SIGNAL ;
    SHAPE ABUTMENT ;
    PORT
      LAYER met2 ;
      RECT 1330.250 1895.420 1330.390 1895.840 ;
    END
  END r0_rd_out[78]
  PIN r0_rd_out[79]
    DIRECTION OUTPUT ;
    USE SIGNAL ;
    SHAPE ABUTMENT ;
    PORT
      LAYER met2 ;
      RECT 1347.270 1895.420 1347.410 1895.840 ;
    END
  END r0_rd_out[79]
  PIN r0_rd_out[80]
    DIRECTION OUTPUT ;
    USE SIGNAL ;
    SHAPE ABUTMENT ;
    PORT
      LAYER met2 ;
      RECT 1364.290 1895.420 1364.430 1895.840 ;
    END
  END r0_rd_out[80]
  PIN r0_rd_out[81]
    DIRECTION OUTPUT ;
    USE SIGNAL ;
    SHAPE ABUTMENT ;
    PORT
      LAYER met2 ;
      RECT 1381.310 1895.420 1381.450 1895.840 ;
    END
  END r0_rd_out[81]
  PIN r0_rd_out[82]
    DIRECTION OUTPUT ;
    USE SIGNAL ;
    SHAPE ABUTMENT ;
    PORT
      LAYER met2 ;
      RECT 1398.330 1895.420 1398.470 1895.840 ;
    END
  END r0_rd_out[82]
  PIN r0_rd_out[83]
    DIRECTION OUTPUT ;
    USE SIGNAL ;
    SHAPE ABUTMENT ;
    PORT
      LAYER met2 ;
      RECT 1415.350 1895.420 1415.490 1895.840 ;
    END
  END r0_rd_out[83]
  PIN r0_rd_out[84]
    DIRECTION OUTPUT ;
    USE SIGNAL ;
    SHAPE ABUTMENT ;
    PORT
      LAYER met2 ;
      RECT 1432.370 1895.420 1432.510 1895.840 ;
    END
  END r0_rd_out[84]
  PIN r0_rd_out[85]
    DIRECTION OUTPUT ;
    USE SIGNAL ;
    SHAPE ABUTMENT ;
    PORT
      LAYER met2 ;
      RECT 1449.390 1895.420 1449.530 1895.840 ;
    END
  END r0_rd_out[85]
  PIN r0_rd_out[86]
    DIRECTION OUTPUT ;
    USE SIGNAL ;
    SHAPE ABUTMENT ;
    PORT
      LAYER met2 ;
      RECT 1466.410 1895.420 1466.550 1895.840 ;
    END
  END r0_rd_out[86]
  PIN r0_rd_out[87]
    DIRECTION OUTPUT ;
    USE SIGNAL ;
    SHAPE ABUTMENT ;
    PORT
      LAYER met2 ;
      RECT 1483.430 1895.420 1483.570 1895.840 ;
    END
  END r0_rd_out[87]
  PIN r0_rd_out[88]
    DIRECTION OUTPUT ;
    USE SIGNAL ;
    SHAPE ABUTMENT ;
    PORT
      LAYER met2 ;
      RECT 1500.450 1895.420 1500.590 1895.840 ;
    END
  END r0_rd_out[88]
  PIN r0_rd_out[89]
    DIRECTION OUTPUT ;
    USE SIGNAL ;
    SHAPE ABUTMENT ;
    PORT
      LAYER met2 ;
      RECT 1517.470 1895.420 1517.610 1895.840 ;
    END
  END r0_rd_out[89]
  PIN r0_rd_out[90]
    DIRECTION OUTPUT ;
    USE SIGNAL ;
    SHAPE ABUTMENT ;
    PORT
      LAYER met2 ;
      RECT 1534.490 1895.420 1534.630 1895.840 ;
    END
  END r0_rd_out[90]
  PIN r0_rd_out[91]
    DIRECTION OUTPUT ;
    USE SIGNAL ;
    SHAPE ABUTMENT ;
    PORT
      LAYER met2 ;
      RECT 1551.510 1895.420 1551.650 1895.840 ;
    END
  END r0_rd_out[91]
  PIN r0_rd_out[92]
    DIRECTION OUTPUT ;
    USE SIGNAL ;
    SHAPE ABUTMENT ;
    PORT
      LAYER met2 ;
      RECT 1568.530 1895.420 1568.670 1895.840 ;
    END
  END r0_rd_out[92]
  PIN r0_rd_out[93]
    DIRECTION OUTPUT ;
    USE SIGNAL ;
    SHAPE ABUTMENT ;
    PORT
      LAYER met2 ;
      RECT 1585.550 1895.420 1585.690 1895.840 ;
    END
  END r0_rd_out[93]
  PIN r0_rd_out[94]
    DIRECTION OUTPUT ;
    USE SIGNAL ;
    SHAPE ABUTMENT ;
    PORT
      LAYER met2 ;
      RECT 1602.570 1895.420 1602.710 1895.840 ;
    END
  END r0_rd_out[94]
  PIN r0_rd_out[95]
    DIRECTION OUTPUT ;
    USE SIGNAL ;
    SHAPE ABUTMENT ;
    PORT
      LAYER met2 ;
      RECT 1619.590 1895.420 1619.730 1895.840 ;
    END
  END r0_rd_out[95]
  PIN r0_rd_out[96]
    DIRECTION OUTPUT ;
    USE SIGNAL ;
    SHAPE ABUTMENT ;
    PORT
      LAYER met2 ;
      RECT 1636.610 1895.420 1636.750 1895.840 ;
    END
  END r0_rd_out[96]
  PIN r0_rd_out[97]
    DIRECTION OUTPUT ;
    USE SIGNAL ;
    SHAPE ABUTMENT ;
    PORT
      LAYER met2 ;
      RECT 1653.630 1895.420 1653.770 1895.840 ;
    END
  END r0_rd_out[97]
  PIN r0_rd_out[98]
    DIRECTION OUTPUT ;
    USE SIGNAL ;
    SHAPE ABUTMENT ;
    PORT
      LAYER met2 ;
      RECT 1670.650 1895.420 1670.790 1895.840 ;
    END
  END r0_rd_out[98]
  PIN r0_rd_out[99]
    DIRECTION OUTPUT ;
    USE SIGNAL ;
    SHAPE ABUTMENT ;
    PORT
      LAYER met2 ;
      RECT 1687.670 1895.420 1687.810 1895.840 ;
    END
  END r0_rd_out[99]
  PIN r0_rd_out[100]
    DIRECTION OUTPUT ;
    USE SIGNAL ;
    SHAPE ABUTMENT ;
    PORT
      LAYER met2 ;
      RECT 1704.690 1895.420 1704.830 1895.840 ;
    END
  END r0_rd_out[100]
  PIN r0_rd_out[101]
    DIRECTION OUTPUT ;
    USE SIGNAL ;
    SHAPE ABUTMENT ;
    PORT
      LAYER met2 ;
      RECT 1721.710 1895.420 1721.850 1895.840 ;
    END
  END r0_rd_out[101]
  PIN r0_rd_out[102]
    DIRECTION OUTPUT ;
    USE SIGNAL ;
    SHAPE ABUTMENT ;
    PORT
      LAYER met2 ;
      RECT 1738.730 1895.420 1738.870 1895.840 ;
    END
  END r0_rd_out[102]
  PIN r0_rd_out[103]
    DIRECTION OUTPUT ;
    USE SIGNAL ;
    SHAPE ABUTMENT ;
    PORT
      LAYER met2 ;
      RECT 1755.750 1895.420 1755.890 1895.840 ;
    END
  END r0_rd_out[103]
  PIN r0_rd_out[104]
    DIRECTION OUTPUT ;
    USE SIGNAL ;
    SHAPE ABUTMENT ;
    PORT
      LAYER met2 ;
      RECT 1772.770 1895.420 1772.910 1895.840 ;
    END
  END r0_rd_out[104]
  PIN r0_rd_out[105]
    DIRECTION OUTPUT ;
    USE SIGNAL ;
    SHAPE ABUTMENT ;
    PORT
      LAYER met2 ;
      RECT 1789.790 1895.420 1789.930 1895.840 ;
    END
  END r0_rd_out[105]
  PIN r0_rd_out[106]
    DIRECTION OUTPUT ;
    USE SIGNAL ;
    SHAPE ABUTMENT ;
    PORT
      LAYER met2 ;
      RECT 1806.810 1895.420 1806.950 1895.840 ;
    END
  END r0_rd_out[106]
  PIN r0_rd_out[107]
    DIRECTION OUTPUT ;
    USE SIGNAL ;
    SHAPE ABUTMENT ;
    PORT
      LAYER met2 ;
      RECT 1823.830 1895.420 1823.970 1895.840 ;
    END
  END r0_rd_out[107]
  PIN r0_rd_out[108]
    DIRECTION OUTPUT ;
    USE SIGNAL ;
    SHAPE ABUTMENT ;
    PORT
      LAYER met2 ;
      RECT 1840.850 1895.420 1840.990 1895.840 ;
    END
  END r0_rd_out[108]
  PIN r0_rd_out[109]
    DIRECTION OUTPUT ;
    USE SIGNAL ;
    SHAPE ABUTMENT ;
    PORT
      LAYER met2 ;
      RECT 1857.870 1895.420 1858.010 1895.840 ;
    END
  END r0_rd_out[109]
  PIN r0_rd_out[110]
    DIRECTION OUTPUT ;
    USE SIGNAL ;
    SHAPE ABUTMENT ;
    PORT
      LAYER met2 ;
      RECT 1874.890 1895.420 1875.030 1895.840 ;
    END
  END r0_rd_out[110]
  PIN r0_rd_out[111]
    DIRECTION OUTPUT ;
    USE SIGNAL ;
    SHAPE ABUTMENT ;
    PORT
      LAYER met2 ;
      RECT 1891.910 1895.420 1892.050 1895.840 ;
    END
  END r0_rd_out[111]
  PIN r0_rd_out[112]
    DIRECTION OUTPUT ;
    USE SIGNAL ;
    SHAPE ABUTMENT ;
    PORT
      LAYER met2 ;
      RECT 1908.930 1895.420 1909.070 1895.840 ;
    END
  END r0_rd_out[112]
  PIN r0_rd_out[113]
    DIRECTION OUTPUT ;
    USE SIGNAL ;
    SHAPE ABUTMENT ;
    PORT
      LAYER met2 ;
      RECT 1925.950 1895.420 1926.090 1895.840 ;
    END
  END r0_rd_out[113]
  PIN r0_rd_out[114]
    DIRECTION OUTPUT ;
    USE SIGNAL ;
    SHAPE ABUTMENT ;
    PORT
      LAYER met2 ;
      RECT 1942.970 1895.420 1943.110 1895.840 ;
    END
  END r0_rd_out[114]
  PIN r0_rd_out[115]
    DIRECTION OUTPUT ;
    USE SIGNAL ;
    SHAPE ABUTMENT ;
    PORT
      LAYER met2 ;
      RECT 1959.990 1895.420 1960.130 1895.840 ;
    END
  END r0_rd_out[115]
  PIN r0_rd_out[116]
    DIRECTION OUTPUT ;
    USE SIGNAL ;
    SHAPE ABUTMENT ;
    PORT
      LAYER met2 ;
      RECT 1977.010 1895.420 1977.150 1895.840 ;
    END
  END r0_rd_out[116]
  PIN r0_rd_out[117]
    DIRECTION OUTPUT ;
    USE SIGNAL ;
    SHAPE ABUTMENT ;
    PORT
      LAYER met2 ;
      RECT 1994.030 1895.420 1994.170 1895.840 ;
    END
  END r0_rd_out[117]
  PIN r0_rd_out[118]
    DIRECTION OUTPUT ;
    USE SIGNAL ;
    SHAPE ABUTMENT ;
    PORT
      LAYER met2 ;
      RECT 2011.050 1895.420 2011.190 1895.840 ;
    END
  END r0_rd_out[118]
  PIN r0_rd_out[119]
    DIRECTION OUTPUT ;
    USE SIGNAL ;
    SHAPE ABUTMENT ;
    PORT
      LAYER met2 ;
      RECT 2028.070 1895.420 2028.210 1895.840 ;
    END
  END r0_rd_out[119]
  PIN r0_rd_out[120]
    DIRECTION OUTPUT ;
    USE SIGNAL ;
    SHAPE ABUTMENT ;
    PORT
      LAYER met2 ;
      RECT 2045.090 1895.420 2045.230 1895.840 ;
    END
  END r0_rd_out[120]
  PIN r0_rd_out[121]
    DIRECTION OUTPUT ;
    USE SIGNAL ;
    SHAPE ABUTMENT ;
    PORT
      LAYER met2 ;
      RECT 2062.110 1895.420 2062.250 1895.840 ;
    END
  END r0_rd_out[121]
  PIN r0_rd_out[122]
    DIRECTION OUTPUT ;
    USE SIGNAL ;
    SHAPE ABUTMENT ;
    PORT
      LAYER met2 ;
      RECT 2079.130 1895.420 2079.270 1895.840 ;
    END
  END r0_rd_out[122]
  PIN r0_rd_out[123]
    DIRECTION OUTPUT ;
    USE SIGNAL ;
    SHAPE ABUTMENT ;
    PORT
      LAYER met2 ;
      RECT 2096.150 1895.420 2096.290 1895.840 ;
    END
  END r0_rd_out[123]
  PIN r0_rd_out[124]
    DIRECTION OUTPUT ;
    USE SIGNAL ;
    SHAPE ABUTMENT ;
    PORT
      LAYER met2 ;
      RECT 2113.170 1895.420 2113.310 1895.840 ;
    END
  END r0_rd_out[124]
  PIN r0_rd_out[125]
    DIRECTION OUTPUT ;
    USE SIGNAL ;
    SHAPE ABUTMENT ;
    PORT
      LAYER met2 ;
      RECT 2130.190 1895.420 2130.330 1895.840 ;
    END
  END r0_rd_out[125]
  PIN r0_rd_out[126]
    DIRECTION OUTPUT ;
    USE SIGNAL ;
    SHAPE ABUTMENT ;
    PORT
      LAYER met2 ;
      RECT 2147.210 1895.420 2147.350 1895.840 ;
    END
  END r0_rd_out[126]
  PIN r0_rd_out[127]
    DIRECTION OUTPUT ;
    USE SIGNAL ;
    SHAPE ABUTMENT ;
    PORT
      LAYER met2 ;
      RECT 2164.230 1895.420 2164.370 1895.840 ;
    END
  END r0_rd_out[127]
  PIN r0_rd_out[128]
    DIRECTION OUTPUT ;
    USE SIGNAL ;
    SHAPE ABUTMENT ;
    PORT
      LAYER met2 ;
      RECT 2181.250 1895.420 2181.390 1895.840 ;
    END
  END r0_rd_out[128]
  PIN r0_rd_out[129]
    DIRECTION OUTPUT ;
    USE SIGNAL ;
    SHAPE ABUTMENT ;
    PORT
      LAYER met2 ;
      RECT 2198.270 1895.420 2198.410 1895.840 ;
    END
  END r0_rd_out[129]
  PIN rw0_addr_in[0]
    DIRECTION INPUT ;
    USE SIGNAL ;
    SHAPE ABUTMENT ;
    PORT
      LAYER met3 ;
      RECT 0.000 1440.090 0.900 1440.390 ;
    END
  END rw0_addr_in[0]
  PIN rw0_addr_in[1]
    DIRECTION INPUT ;
    USE SIGNAL ;
    SHAPE ABUTMENT ;
    PORT
      LAYER met3 ;
      RECT 0.000 1483.610 0.900 1483.910 ;
    END
  END rw0_addr_in[1]
  PIN rw0_addr_in[2]
    DIRECTION INPUT ;
    USE SIGNAL ;
    SHAPE ABUTMENT ;
    PORT
      LAYER met3 ;
      RECT 0.000 1527.130 0.900 1527.430 ;
    END
  END rw0_addr_in[2]
  PIN rw0_addr_in[3]
    DIRECTION INPUT ;
    USE SIGNAL ;
    SHAPE ABUTMENT ;
    PORT
      LAYER met3 ;
      RECT 0.000 1570.650 0.900 1570.950 ;
    END
  END rw0_addr_in[3]
  PIN rw0_addr_in[4]
    DIRECTION INPUT ;
    USE SIGNAL ;
    SHAPE ABUTMENT ;
    PORT
      LAYER met3 ;
      RECT 0.000 1614.170 0.900 1614.470 ;
    END
  END rw0_addr_in[4]
  PIN rw0_addr_in[5]
    DIRECTION INPUT ;
    USE SIGNAL ;
    SHAPE ABUTMENT ;
    PORT
      LAYER met3 ;
      RECT 2363.960 1396.570 2364.860 1396.870 ;
    END
  END rw0_addr_in[5]
  PIN rw0_addr_in[6]
    DIRECTION INPUT ;
    USE SIGNAL ;
    SHAPE ABUTMENT ;
    PORT
      LAYER met3 ;
      RECT 2363.960 1440.090 2364.860 1440.390 ;
    END
  END rw0_addr_in[6]
  PIN rw0_addr_in[7]
    DIRECTION INPUT ;
    USE SIGNAL ;
    SHAPE ABUTMENT ;
    PORT
      LAYER met3 ;
      RECT 2363.960 1483.610 2364.860 1483.910 ;
    END
  END rw0_addr_in[7]
  PIN rw0_addr_in[8]
    DIRECTION INPUT ;
    USE SIGNAL ;
    SHAPE ABUTMENT ;
    PORT
      LAYER met3 ;
      RECT 2363.960 1527.130 2364.860 1527.430 ;
    END
  END rw0_addr_in[8]
  PIN rw0_addr_in[9]
    DIRECTION INPUT ;
    USE SIGNAL ;
    SHAPE ABUTMENT ;
    PORT
      LAYER met3 ;
      RECT 2363.960 1570.650 2364.860 1570.950 ;
    END
  END rw0_addr_in[9]
  PIN r0_addr_in[0]
    DIRECTION INPUT ;
    USE SIGNAL ;
    SHAPE ABUTMENT ;
    PORT
      LAYER met3 ;
      RECT 0.000 1657.690 0.900 1657.990 ;
    END
  END r0_addr_in[0]
  PIN r0_addr_in[1]
    DIRECTION INPUT ;
    USE SIGNAL ;
    SHAPE ABUTMENT ;
    PORT
      LAYER met3 ;
      RECT 0.000 1701.210 0.900 1701.510 ;
    END
  END r0_addr_in[1]
  PIN r0_addr_in[2]
    DIRECTION INPUT ;
    USE SIGNAL ;
    SHAPE ABUTMENT ;
    PORT
      LAYER met3 ;
      RECT 0.000 1744.730 0.900 1745.030 ;
    END
  END r0_addr_in[2]
  PIN r0_addr_in[3]
    DIRECTION INPUT ;
    USE SIGNAL ;
    SHAPE ABUTMENT ;
    PORT
      LAYER met3 ;
      RECT 0.000 1788.250 0.900 1788.550 ;
    END
  END r0_addr_in[3]
  PIN r0_addr_in[4]
    DIRECTION INPUT ;
    USE SIGNAL ;
    SHAPE ABUTMENT ;
    PORT
      LAYER met3 ;
      RECT 0.000 1831.770 0.900 1832.070 ;
    END
  END r0_addr_in[4]
  PIN r0_addr_in[5]
    DIRECTION INPUT ;
    USE SIGNAL ;
    SHAPE ABUTMENT ;
    PORT
      LAYER met3 ;
      RECT 2363.960 1614.170 2364.860 1614.470 ;
    END
  END r0_addr_in[5]
  PIN r0_addr_in[6]
    DIRECTION INPUT ;
    USE SIGNAL ;
    SHAPE ABUTMENT ;
    PORT
      LAYER met3 ;
      RECT 2363.960 1657.690 2364.860 1657.990 ;
    END
  END r0_addr_in[6]
  PIN r0_addr_in[7]
    DIRECTION INPUT ;
    USE SIGNAL ;
    SHAPE ABUTMENT ;
    PORT
      LAYER met3 ;
      RECT 2363.960 1701.210 2364.860 1701.510 ;
    END
  END r0_addr_in[7]
  PIN r0_addr_in[8]
    DIRECTION INPUT ;
    USE SIGNAL ;
    SHAPE ABUTMENT ;
    PORT
      LAYER met3 ;
      RECT 2363.960 1744.730 2364.860 1745.030 ;
    END
  END r0_addr_in[8]
  PIN r0_addr_in[9]
    DIRECTION INPUT ;
    USE SIGNAL ;
    SHAPE ABUTMENT ;
    PORT
      LAYER met3 ;
      RECT 2363.960 1788.250 2364.860 1788.550 ;
    END
  END r0_addr_in[9]
  PIN rw0_we_in
    DIRECTION INPUT ;
    USE SIGNAL ;
    SHAPE ABUTMENT ;
    PORT
      LAYER met2 ;
      RECT 2215.290 1895.420 2215.430 1895.840 ;
    END
  END rw0_we_in
  PIN rw0_ce_in
    DIRECTION INPUT ;
    USE SIGNAL ;
    SHAPE ABUTMENT ;
    PORT
      LAYER met2 ;
      RECT 2232.310 1895.420 2232.450 1895.840 ;
    END
  END rw0_ce_in
  PIN rw0_clk
    DIRECTION INPUT ;
    USE SIGNAL ;
    SHAPE ABUTMENT ;
    PORT
      LAYER met2 ;
      RECT 2249.330 1895.420 2249.470 1895.840 ;
    END
  END rw0_clk
  PIN r0_ce_in
    DIRECTION INPUT ;
    USE SIGNAL ;
    SHAPE ABUTMENT ;
    PORT
      LAYER met2 ;
      RECT 2266.350 1895.420 2266.490 1895.840 ;
    END
  END r0_ce_in
  PIN r0_clk
    DIRECTION INPUT ;
    USE SIGNAL ;
    SHAPE ABUTMENT ;
    PORT
      LAYER met2 ;
      RECT 2283.370 1895.420 2283.510 1895.840 ;
    END
  END r0_clk
  PIN VSS
    DIRECTION INOUT ;
    USE GROUND ;
    PORT
      LAYER met4 ;
      RECT 2.160 4.080 3.360 1891.760 ;
      RECT 13.040 4.080 14.240 1891.760 ;
      RECT 23.920 4.080 25.120 1891.760 ;
      RECT 34.800 4.080 36.000 1891.760 ;
      RECT 45.680 4.080 46.880 1891.760 ;
      RECT 56.560 4.080 57.760 1891.760 ;
      RECT 67.440 4.080 68.640 1891.760 ;
      RECT 78.320 4.080 79.520 1891.760 ;
      RECT 89.200 4.080 90.400 1891.760 ;
      RECT 100.080 4.080 101.280 1891.760 ;
      RECT 110.960 4.080 112.160 1891.760 ;
      RECT 121.840 4.080 123.040 1891.760 ;
      RECT 132.720 4.080 133.920 1891.760 ;
      RECT 143.600 4.080 144.800 1891.760 ;
      RECT 154.480 4.080 155.680 1891.760 ;
      RECT 165.360 4.080 166.560 1891.760 ;
      RECT 176.240 4.080 177.440 1891.760 ;
      RECT 187.120 4.080 188.320 1891.760 ;
      RECT 198.000 4.080 199.200 1891.760 ;
      RECT 208.880 4.080 210.080 1891.760 ;
      RECT 219.760 4.080 220.960 1891.760 ;
      RECT 230.640 4.080 231.840 1891.760 ;
      RECT 241.520 4.080 242.720 1891.760 ;
      RECT 252.400 4.080 253.600 1891.760 ;
      RECT 263.280 4.080 264.480 1891.760 ;
      RECT 274.160 4.080 275.360 1891.760 ;
      RECT 285.040 4.080 286.240 1891.760 ;
      RECT 295.920 4.080 297.120 1891.760 ;
      RECT 306.800 4.080 308.000 1891.760 ;
      RECT 317.680 4.080 318.880 1891.760 ;
      RECT 328.560 4.080 329.760 1891.760 ;
      RECT 339.440 4.080 340.640 1891.760 ;
      RECT 350.320 4.080 351.520 1891.760 ;
      RECT 361.200 4.080 362.400 1891.760 ;
      RECT 372.080 4.080 373.280 1891.760 ;
      RECT 382.960 4.080 384.160 1891.760 ;
      RECT 393.840 4.080 395.040 1891.760 ;
      RECT 404.720 4.080 405.920 1891.760 ;
      RECT 415.600 4.080 416.800 1891.760 ;
      RECT 426.480 4.080 427.680 1891.760 ;
      RECT 437.360 4.080 438.560 1891.760 ;
      RECT 448.240 4.080 449.440 1891.760 ;
      RECT 459.120 4.080 460.320 1891.760 ;
      RECT 470.000 4.080 471.200 1891.760 ;
      RECT 480.880 4.080 482.080 1891.760 ;
      RECT 491.760 4.080 492.960 1891.760 ;
      RECT 502.640 4.080 503.840 1891.760 ;
      RECT 513.520 4.080 514.720 1891.760 ;
      RECT 524.400 4.080 525.600 1891.760 ;
      RECT 535.280 4.080 536.480 1891.760 ;
      RECT 546.160 4.080 547.360 1891.760 ;
      RECT 557.040 4.080 558.240 1891.760 ;
      RECT 567.920 4.080 569.120 1891.760 ;
      RECT 578.800 4.080 580.000 1891.760 ;
      RECT 589.680 4.080 590.880 1891.760 ;
      RECT 600.560 4.080 601.760 1891.760 ;
      RECT 611.440 4.080 612.640 1891.760 ;
      RECT 622.320 4.080 623.520 1891.760 ;
      RECT 633.200 4.080 634.400 1891.760 ;
      RECT 644.080 4.080 645.280 1891.760 ;
      RECT 654.960 4.080 656.160 1891.760 ;
      RECT 665.840 4.080 667.040 1891.760 ;
      RECT 676.720 4.080 677.920 1891.760 ;
      RECT 687.600 4.080 688.800 1891.760 ;
      RECT 698.480 4.080 699.680 1891.760 ;
      RECT 709.360 4.080 710.560 1891.760 ;
      RECT 720.240 4.080 721.440 1891.760 ;
      RECT 731.120 4.080 732.320 1891.760 ;
      RECT 742.000 4.080 743.200 1891.760 ;
      RECT 752.880 4.080 754.080 1891.760 ;
      RECT 763.760 4.080 764.960 1891.760 ;
      RECT 774.640 4.080 775.840 1891.760 ;
      RECT 785.520 4.080 786.720 1891.760 ;
      RECT 796.400 4.080 797.600 1891.760 ;
      RECT 807.280 4.080 808.480 1891.760 ;
      RECT 818.160 4.080 819.360 1891.760 ;
      RECT 829.040 4.080 830.240 1891.760 ;
      RECT 839.920 4.080 841.120 1891.760 ;
      RECT 850.800 4.080 852.000 1891.760 ;
      RECT 861.680 4.080 862.880 1891.760 ;
      RECT 872.560 4.080 873.760 1891.760 ;
      RECT 883.440 4.080 884.640 1891.760 ;
      RECT 894.320 4.080 895.520 1891.760 ;
      RECT 905.200 4.080 906.400 1891.760 ;
      RECT 916.080 4.080 917.280 1891.760 ;
      RECT 926.960 4.080 928.160 1891.760 ;
      RECT 937.840 4.080 939.040 1891.760 ;
      RECT 948.720 4.080 949.920 1891.760 ;
      RECT 959.600 4.080 960.800 1891.760 ;
      RECT 970.480 4.080 971.680 1891.760 ;
      RECT 981.360 4.080 982.560 1891.760 ;
      RECT 992.240 4.080 993.440 1891.760 ;
      RECT 1003.120 4.080 1004.320 1891.760 ;
      RECT 1014.000 4.080 1015.200 1891.760 ;
      RECT 1024.880 4.080 1026.080 1891.760 ;
      RECT 1035.760 4.080 1036.960 1891.760 ;
      RECT 1046.640 4.080 1047.840 1891.760 ;
      RECT 1057.520 4.080 1058.720 1891.760 ;
      RECT 1068.400 4.080 1069.600 1891.760 ;
      RECT 1079.280 4.080 1080.480 1891.760 ;
      RECT 1090.160 4.080 1091.360 1891.760 ;
      RECT 1101.040 4.080 1102.240 1891.760 ;
      RECT 1111.920 4.080 1113.120 1891.760 ;
      RECT 1122.800 4.080 1124.000 1891.760 ;
      RECT 1133.680 4.080 1134.880 1891.760 ;
      RECT 1144.560 4.080 1145.760 1891.760 ;
      RECT 1155.440 4.080 1156.640 1891.760 ;
      RECT 1166.320 4.080 1167.520 1891.760 ;
      RECT 1177.200 4.080 1178.400 1891.760 ;
      RECT 1188.080 4.080 1189.280 1891.760 ;
      RECT 1198.960 4.080 1200.160 1891.760 ;
      RECT 1209.840 4.080 1211.040 1891.760 ;
      RECT 1220.720 4.080 1221.920 1891.760 ;
      RECT 1231.600 4.080 1232.800 1891.760 ;
      RECT 1242.480 4.080 1243.680 1891.760 ;
      RECT 1253.360 4.080 1254.560 1891.760 ;
      RECT 1264.240 4.080 1265.440 1891.760 ;
      RECT 1275.120 4.080 1276.320 1891.760 ;
      RECT 1286.000 4.080 1287.200 1891.760 ;
      RECT 1296.880 4.080 1298.080 1891.760 ;
      RECT 1307.760 4.080 1308.960 1891.760 ;
      RECT 1318.640 4.080 1319.840 1891.760 ;
      RECT 1329.520 4.080 1330.720 1891.760 ;
      RECT 1340.400 4.080 1341.600 1891.760 ;
      RECT 1351.280 4.080 1352.480 1891.760 ;
      RECT 1362.160 4.080 1363.360 1891.760 ;
      RECT 1373.040 4.080 1374.240 1891.760 ;
      RECT 1383.920 4.080 1385.120 1891.760 ;
      RECT 1394.800 4.080 1396.000 1891.760 ;
      RECT 1405.680 4.080 1406.880 1891.760 ;
      RECT 1416.560 4.080 1417.760 1891.760 ;
      RECT 1427.440 4.080 1428.640 1891.760 ;
      RECT 1438.320 4.080 1439.520 1891.760 ;
      RECT 1449.200 4.080 1450.400 1891.760 ;
      RECT 1460.080 4.080 1461.280 1891.760 ;
      RECT 1470.960 4.080 1472.160 1891.760 ;
      RECT 1481.840 4.080 1483.040 1891.760 ;
      RECT 1492.720 4.080 1493.920 1891.760 ;
      RECT 1503.600 4.080 1504.800 1891.760 ;
      RECT 1514.480 4.080 1515.680 1891.760 ;
      RECT 1525.360 4.080 1526.560 1891.760 ;
      RECT 1536.240 4.080 1537.440 1891.760 ;
      RECT 1547.120 4.080 1548.320 1891.760 ;
      RECT 1558.000 4.080 1559.200 1891.760 ;
      RECT 1568.880 4.080 1570.080 1891.760 ;
      RECT 1579.760 4.080 1580.960 1891.760 ;
      RECT 1590.640 4.080 1591.840 1891.760 ;
      RECT 1601.520 4.080 1602.720 1891.760 ;
      RECT 1612.400 4.080 1613.600 1891.760 ;
      RECT 1623.280 4.080 1624.480 1891.760 ;
      RECT 1634.160 4.080 1635.360 1891.760 ;
      RECT 1645.040 4.080 1646.240 1891.760 ;
      RECT 1655.920 4.080 1657.120 1891.760 ;
      RECT 1666.800 4.080 1668.000 1891.760 ;
      RECT 1677.680 4.080 1678.880 1891.760 ;
      RECT 1688.560 4.080 1689.760 1891.760 ;
      RECT 1699.440 4.080 1700.640 1891.760 ;
      RECT 1710.320 4.080 1711.520 1891.760 ;
      RECT 1721.200 4.080 1722.400 1891.760 ;
      RECT 1732.080 4.080 1733.280 1891.760 ;
      RECT 1742.960 4.080 1744.160 1891.760 ;
      RECT 1753.840 4.080 1755.040 1891.760 ;
      RECT 1764.720 4.080 1765.920 1891.760 ;
      RECT 1775.600 4.080 1776.800 1891.760 ;
      RECT 1786.480 4.080 1787.680 1891.760 ;
      RECT 1797.360 4.080 1798.560 1891.760 ;
      RECT 1808.240 4.080 1809.440 1891.760 ;
      RECT 1819.120 4.080 1820.320 1891.760 ;
      RECT 1830.000 4.080 1831.200 1891.760 ;
      RECT 1840.880 4.080 1842.080 1891.760 ;
      RECT 1851.760 4.080 1852.960 1891.760 ;
      RECT 1862.640 4.080 1863.840 1891.760 ;
      RECT 1873.520 4.080 1874.720 1891.760 ;
      RECT 1884.400 4.080 1885.600 1891.760 ;
      RECT 1895.280 4.080 1896.480 1891.760 ;
      RECT 1906.160 4.080 1907.360 1891.760 ;
      RECT 1917.040 4.080 1918.240 1891.760 ;
      RECT 1927.920 4.080 1929.120 1891.760 ;
      RECT 1938.800 4.080 1940.000 1891.760 ;
      RECT 1949.680 4.080 1950.880 1891.760 ;
      RECT 1960.560 4.080 1961.760 1891.760 ;
      RECT 1971.440 4.080 1972.640 1891.760 ;
      RECT 1982.320 4.080 1983.520 1891.760 ;
      RECT 1993.200 4.080 1994.400 1891.760 ;
      RECT 2004.080 4.080 2005.280 1891.760 ;
      RECT 2014.960 4.080 2016.160 1891.760 ;
      RECT 2025.840 4.080 2027.040 1891.760 ;
      RECT 2036.720 4.080 2037.920 1891.760 ;
      RECT 2047.600 4.080 2048.800 1891.760 ;
      RECT 2058.480 4.080 2059.680 1891.760 ;
      RECT 2069.360 4.080 2070.560 1891.760 ;
      RECT 2080.240 4.080 2081.440 1891.760 ;
      RECT 2091.120 4.080 2092.320 1891.760 ;
      RECT 2102.000 4.080 2103.200 1891.760 ;
      RECT 2112.880 4.080 2114.080 1891.760 ;
      RECT 2123.760 4.080 2124.960 1891.760 ;
      RECT 2134.640 4.080 2135.840 1891.760 ;
      RECT 2145.520 4.080 2146.720 1891.760 ;
      RECT 2156.400 4.080 2157.600 1891.760 ;
      RECT 2167.280 4.080 2168.480 1891.760 ;
      RECT 2178.160 4.080 2179.360 1891.760 ;
      RECT 2189.040 4.080 2190.240 1891.760 ;
      RECT 2199.920 4.080 2201.120 1891.760 ;
      RECT 2210.800 4.080 2212.000 1891.760 ;
      RECT 2221.680 4.080 2222.880 1891.760 ;
      RECT 2232.560 4.080 2233.760 1891.760 ;
      RECT 2243.440 4.080 2244.640 1891.760 ;
      RECT 2254.320 4.080 2255.520 1891.760 ;
      RECT 2265.200 4.080 2266.400 1891.760 ;
      RECT 2276.080 4.080 2277.280 1891.760 ;
      RECT 2286.960 4.080 2288.160 1891.760 ;
      RECT 2297.840 4.080 2299.040 1891.760 ;
      RECT 2308.720 4.080 2309.920 1891.760 ;
      RECT 2319.600 4.080 2320.800 1891.760 ;
      RECT 2330.480 4.080 2331.680 1891.760 ;
      RECT 2341.360 4.080 2342.560 1891.760 ;
      RECT 2352.240 4.080 2353.440 1891.760 ;
      RECT 2363.120 4.080 2364.320 1891.760 ;
    END
  END VSS
  PIN VDD
    DIRECTION INOUT ;
    USE POWER ;
    PORT
      LAYER met4 ;
      RECT 2.160 4.080 3.360 1891.760 ;
      RECT 13.040 4.080 14.240 1891.760 ;
      RECT 23.920 4.080 25.120 1891.760 ;
      RECT 34.800 4.080 36.000 1891.760 ;
      RECT 45.680 4.080 46.880 1891.760 ;
      RECT 56.560 4.080 57.760 1891.760 ;
      RECT 67.440 4.080 68.640 1891.760 ;
      RECT 78.320 4.080 79.520 1891.760 ;
      RECT 89.200 4.080 90.400 1891.760 ;
      RECT 100.080 4.080 101.280 1891.760 ;
      RECT 110.960 4.080 112.160 1891.760 ;
      RECT 121.840 4.080 123.040 1891.760 ;
      RECT 132.720 4.080 133.920 1891.760 ;
      RECT 143.600 4.080 144.800 1891.760 ;
      RECT 154.480 4.080 155.680 1891.760 ;
      RECT 165.360 4.080 166.560 1891.760 ;
      RECT 176.240 4.080 177.440 1891.760 ;
      RECT 187.120 4.080 188.320 1891.760 ;
      RECT 198.000 4.080 199.200 1891.760 ;
      RECT 208.880 4.080 210.080 1891.760 ;
      RECT 219.760 4.080 220.960 1891.760 ;
      RECT 230.640 4.080 231.840 1891.760 ;
      RECT 241.520 4.080 242.720 1891.760 ;
      RECT 252.400 4.080 253.600 1891.760 ;
      RECT 263.280 4.080 264.480 1891.760 ;
      RECT 274.160 4.080 275.360 1891.760 ;
      RECT 285.040 4.080 286.240 1891.760 ;
      RECT 295.920 4.080 297.120 1891.760 ;
      RECT 306.800 4.080 308.000 1891.760 ;
      RECT 317.680 4.080 318.880 1891.760 ;
      RECT 328.560 4.080 329.760 1891.760 ;
      RECT 339.440 4.080 340.640 1891.760 ;
      RECT 350.320 4.080 351.520 1891.760 ;
      RECT 361.200 4.080 362.400 1891.760 ;
      RECT 372.080 4.080 373.280 1891.760 ;
      RECT 382.960 4.080 384.160 1891.760 ;
      RECT 393.840 4.080 395.040 1891.760 ;
      RECT 404.720 4.080 405.920 1891.760 ;
      RECT 415.600 4.080 416.800 1891.760 ;
      RECT 426.480 4.080 427.680 1891.760 ;
      RECT 437.360 4.080 438.560 1891.760 ;
      RECT 448.240 4.080 449.440 1891.760 ;
      RECT 459.120 4.080 460.320 1891.760 ;
      RECT 470.000 4.080 471.200 1891.760 ;
      RECT 480.880 4.080 482.080 1891.760 ;
      RECT 491.760 4.080 492.960 1891.760 ;
      RECT 502.640 4.080 503.840 1891.760 ;
      RECT 513.520 4.080 514.720 1891.760 ;
      RECT 524.400 4.080 525.600 1891.760 ;
      RECT 535.280 4.080 536.480 1891.760 ;
      RECT 546.160 4.080 547.360 1891.760 ;
      RECT 557.040 4.080 558.240 1891.760 ;
      RECT 567.920 4.080 569.120 1891.760 ;
      RECT 578.800 4.080 580.000 1891.760 ;
      RECT 589.680 4.080 590.880 1891.760 ;
      RECT 600.560 4.080 601.760 1891.760 ;
      RECT 611.440 4.080 612.640 1891.760 ;
      RECT 622.320 4.080 623.520 1891.760 ;
      RECT 633.200 4.080 634.400 1891.760 ;
      RECT 644.080 4.080 645.280 1891.760 ;
      RECT 654.960 4.080 656.160 1891.760 ;
      RECT 665.840 4.080 667.040 1891.760 ;
      RECT 676.720 4.080 677.920 1891.760 ;
      RECT 687.600 4.080 688.800 1891.760 ;
      RECT 698.480 4.080 699.680 1891.760 ;
      RECT 709.360 4.080 710.560 1891.760 ;
      RECT 720.240 4.080 721.440 1891.760 ;
      RECT 731.120 4.080 732.320 1891.760 ;
      RECT 742.000 4.080 743.200 1891.760 ;
      RECT 752.880 4.080 754.080 1891.760 ;
      RECT 763.760 4.080 764.960 1891.760 ;
      RECT 774.640 4.080 775.840 1891.760 ;
      RECT 785.520 4.080 786.720 1891.760 ;
      RECT 796.400 4.080 797.600 1891.760 ;
      RECT 807.280 4.080 808.480 1891.760 ;
      RECT 818.160 4.080 819.360 1891.760 ;
      RECT 829.040 4.080 830.240 1891.760 ;
      RECT 839.920 4.080 841.120 1891.760 ;
      RECT 850.800 4.080 852.000 1891.760 ;
      RECT 861.680 4.080 862.880 1891.760 ;
      RECT 872.560 4.080 873.760 1891.760 ;
      RECT 883.440 4.080 884.640 1891.760 ;
      RECT 894.320 4.080 895.520 1891.760 ;
      RECT 905.200 4.080 906.400 1891.760 ;
      RECT 916.080 4.080 917.280 1891.760 ;
      RECT 926.960 4.080 928.160 1891.760 ;
      RECT 937.840 4.080 939.040 1891.760 ;
      RECT 948.720 4.080 949.920 1891.760 ;
      RECT 959.600 4.080 960.800 1891.760 ;
      RECT 970.480 4.080 971.680 1891.760 ;
      RECT 981.360 4.080 982.560 1891.760 ;
      RECT 992.240 4.080 993.440 1891.760 ;
      RECT 1003.120 4.080 1004.320 1891.760 ;
      RECT 1014.000 4.080 1015.200 1891.760 ;
      RECT 1024.880 4.080 1026.080 1891.760 ;
      RECT 1035.760 4.080 1036.960 1891.760 ;
      RECT 1046.640 4.080 1047.840 1891.760 ;
      RECT 1057.520 4.080 1058.720 1891.760 ;
      RECT 1068.400 4.080 1069.600 1891.760 ;
      RECT 1079.280 4.080 1080.480 1891.760 ;
      RECT 1090.160 4.080 1091.360 1891.760 ;
      RECT 1101.040 4.080 1102.240 1891.760 ;
      RECT 1111.920 4.080 1113.120 1891.760 ;
      RECT 1122.800 4.080 1124.000 1891.760 ;
      RECT 1133.680 4.080 1134.880 1891.760 ;
      RECT 1144.560 4.080 1145.760 1891.760 ;
      RECT 1155.440 4.080 1156.640 1891.760 ;
      RECT 1166.320 4.080 1167.520 1891.760 ;
      RECT 1177.200 4.080 1178.400 1891.760 ;
      RECT 1188.080 4.080 1189.280 1891.760 ;
      RECT 1198.960 4.080 1200.160 1891.760 ;
      RECT 1209.840 4.080 1211.040 1891.760 ;
      RECT 1220.720 4.080 1221.920 1891.760 ;
      RECT 1231.600 4.080 1232.800 1891.760 ;
      RECT 1242.480 4.080 1243.680 1891.760 ;
      RECT 1253.360 4.080 1254.560 1891.760 ;
      RECT 1264.240 4.080 1265.440 1891.760 ;
      RECT 1275.120 4.080 1276.320 1891.760 ;
      RECT 1286.000 4.080 1287.200 1891.760 ;
      RECT 1296.880 4.080 1298.080 1891.760 ;
      RECT 1307.760 4.080 1308.960 1891.760 ;
      RECT 1318.640 4.080 1319.840 1891.760 ;
      RECT 1329.520 4.080 1330.720 1891.760 ;
      RECT 1340.400 4.080 1341.600 1891.760 ;
      RECT 1351.280 4.080 1352.480 1891.760 ;
      RECT 1362.160 4.080 1363.360 1891.760 ;
      RECT 1373.040 4.080 1374.240 1891.760 ;
      RECT 1383.920 4.080 1385.120 1891.760 ;
      RECT 1394.800 4.080 1396.000 1891.760 ;
      RECT 1405.680 4.080 1406.880 1891.760 ;
      RECT 1416.560 4.080 1417.760 1891.760 ;
      RECT 1427.440 4.080 1428.640 1891.760 ;
      RECT 1438.320 4.080 1439.520 1891.760 ;
      RECT 1449.200 4.080 1450.400 1891.760 ;
      RECT 1460.080 4.080 1461.280 1891.760 ;
      RECT 1470.960 4.080 1472.160 1891.760 ;
      RECT 1481.840 4.080 1483.040 1891.760 ;
      RECT 1492.720 4.080 1493.920 1891.760 ;
      RECT 1503.600 4.080 1504.800 1891.760 ;
      RECT 1514.480 4.080 1515.680 1891.760 ;
      RECT 1525.360 4.080 1526.560 1891.760 ;
      RECT 1536.240 4.080 1537.440 1891.760 ;
      RECT 1547.120 4.080 1548.320 1891.760 ;
      RECT 1558.000 4.080 1559.200 1891.760 ;
      RECT 1568.880 4.080 1570.080 1891.760 ;
      RECT 1579.760 4.080 1580.960 1891.760 ;
      RECT 1590.640 4.080 1591.840 1891.760 ;
      RECT 1601.520 4.080 1602.720 1891.760 ;
      RECT 1612.400 4.080 1613.600 1891.760 ;
      RECT 1623.280 4.080 1624.480 1891.760 ;
      RECT 1634.160 4.080 1635.360 1891.760 ;
      RECT 1645.040 4.080 1646.240 1891.760 ;
      RECT 1655.920 4.080 1657.120 1891.760 ;
      RECT 1666.800 4.080 1668.000 1891.760 ;
      RECT 1677.680 4.080 1678.880 1891.760 ;
      RECT 1688.560 4.080 1689.760 1891.760 ;
      RECT 1699.440 4.080 1700.640 1891.760 ;
      RECT 1710.320 4.080 1711.520 1891.760 ;
      RECT 1721.200 4.080 1722.400 1891.760 ;
      RECT 1732.080 4.080 1733.280 1891.760 ;
      RECT 1742.960 4.080 1744.160 1891.760 ;
      RECT 1753.840 4.080 1755.040 1891.760 ;
      RECT 1764.720 4.080 1765.920 1891.760 ;
      RECT 1775.600 4.080 1776.800 1891.760 ;
      RECT 1786.480 4.080 1787.680 1891.760 ;
      RECT 1797.360 4.080 1798.560 1891.760 ;
      RECT 1808.240 4.080 1809.440 1891.760 ;
      RECT 1819.120 4.080 1820.320 1891.760 ;
      RECT 1830.000 4.080 1831.200 1891.760 ;
      RECT 1840.880 4.080 1842.080 1891.760 ;
      RECT 1851.760 4.080 1852.960 1891.760 ;
      RECT 1862.640 4.080 1863.840 1891.760 ;
      RECT 1873.520 4.080 1874.720 1891.760 ;
      RECT 1884.400 4.080 1885.600 1891.760 ;
      RECT 1895.280 4.080 1896.480 1891.760 ;
      RECT 1906.160 4.080 1907.360 1891.760 ;
      RECT 1917.040 4.080 1918.240 1891.760 ;
      RECT 1927.920 4.080 1929.120 1891.760 ;
      RECT 1938.800 4.080 1940.000 1891.760 ;
      RECT 1949.680 4.080 1950.880 1891.760 ;
      RECT 1960.560 4.080 1961.760 1891.760 ;
      RECT 1971.440 4.080 1972.640 1891.760 ;
      RECT 1982.320 4.080 1983.520 1891.760 ;
      RECT 1993.200 4.080 1994.400 1891.760 ;
      RECT 2004.080 4.080 2005.280 1891.760 ;
      RECT 2014.960 4.080 2016.160 1891.760 ;
      RECT 2025.840 4.080 2027.040 1891.760 ;
      RECT 2036.720 4.080 2037.920 1891.760 ;
      RECT 2047.600 4.080 2048.800 1891.760 ;
      RECT 2058.480 4.080 2059.680 1891.760 ;
      RECT 2069.360 4.080 2070.560 1891.760 ;
      RECT 2080.240 4.080 2081.440 1891.760 ;
      RECT 2091.120 4.080 2092.320 1891.760 ;
      RECT 2102.000 4.080 2103.200 1891.760 ;
      RECT 2112.880 4.080 2114.080 1891.760 ;
      RECT 2123.760 4.080 2124.960 1891.760 ;
      RECT 2134.640 4.080 2135.840 1891.760 ;
      RECT 2145.520 4.080 2146.720 1891.760 ;
      RECT 2156.400 4.080 2157.600 1891.760 ;
      RECT 2167.280 4.080 2168.480 1891.760 ;
      RECT 2178.160 4.080 2179.360 1891.760 ;
      RECT 2189.040 4.080 2190.240 1891.760 ;
      RECT 2199.920 4.080 2201.120 1891.760 ;
      RECT 2210.800 4.080 2212.000 1891.760 ;
      RECT 2221.680 4.080 2222.880 1891.760 ;
      RECT 2232.560 4.080 2233.760 1891.760 ;
      RECT 2243.440 4.080 2244.640 1891.760 ;
      RECT 2254.320 4.080 2255.520 1891.760 ;
      RECT 2265.200 4.080 2266.400 1891.760 ;
      RECT 2276.080 4.080 2277.280 1891.760 ;
      RECT 2286.960 4.080 2288.160 1891.760 ;
      RECT 2297.840 4.080 2299.040 1891.760 ;
      RECT 2308.720 4.080 2309.920 1891.760 ;
      RECT 2319.600 4.080 2320.800 1891.760 ;
      RECT 2330.480 4.080 2331.680 1891.760 ;
      RECT 2341.360 4.080 2342.560 1891.760 ;
      RECT 2352.240 4.080 2353.440 1891.760 ;
      RECT 2363.120 4.080 2364.320 1891.760 ;
    END
  END VDD
  OBS
    LAYER met1 ;
    RECT 0 0 2364.860 1895.840 ;
    LAYER met2 ;
    RECT 0 0 2364.860 1895.840 ;
    LAYER met3 ;
    RECT 0 0 2364.860 1895.840 ;
    LAYER met4 ;
    RECT 0 0 2364.860 1895.840 ;
  END
END fakeram130_1rw1r_130w1024d

END LIBRARY
